VERSION 5.8 ;
BUSBITCHARS "[]" ;
DIVIDERCHAR "/" ;
UNITS
    DATABASE MICRONS 1000 ;
END UNITS

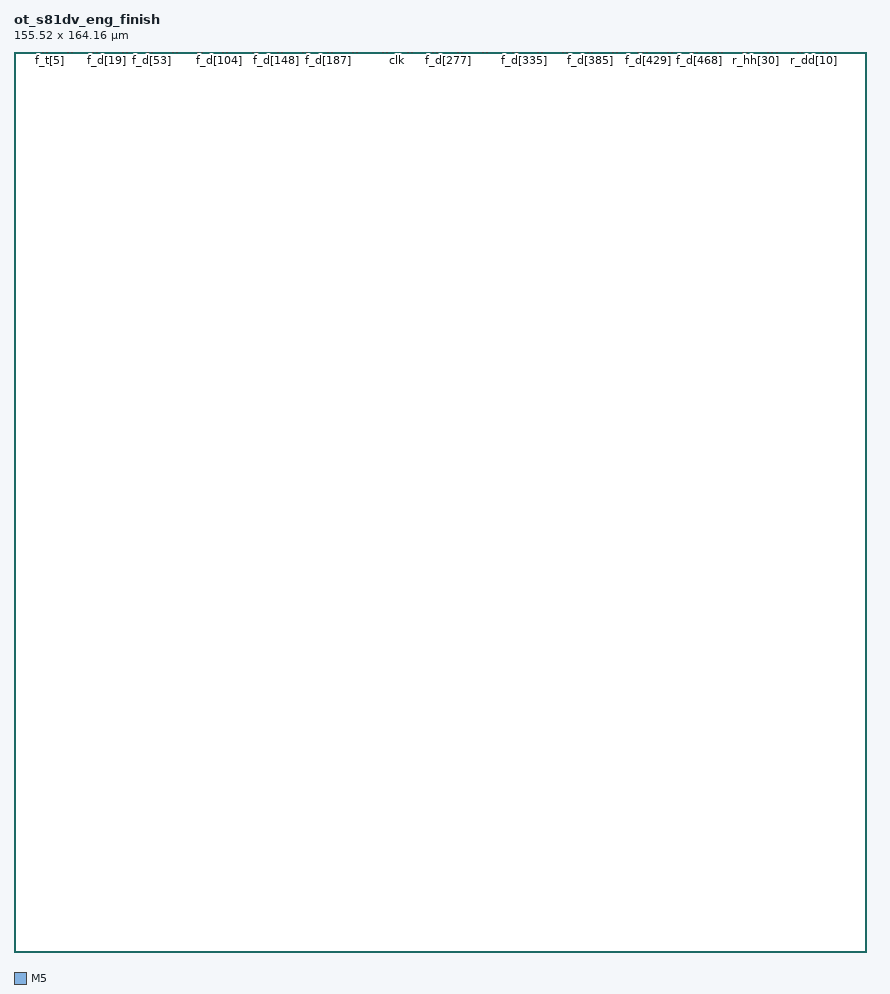
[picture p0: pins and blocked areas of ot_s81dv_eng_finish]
MACRO ot_s81dv_eng_finish
  FOREIGN ot_s81dv_eng_finish 0 0 ;
  CLASS BLOCK ;
  SIZE 155.52 BY 164.16 ;
  PIN go
    DIRECTION INPUT ;
    USE SIGNAL ;
    PORT
      LAYER M5 ;
        RECT 4.3200 164.0760 4.3440 164.1600 ;
    END
  END go
  PIN f_v[0]
    DIRECTION INPUT ;
    USE SIGNAL ;
    PORT
      LAYER M5 ;
        RECT 4.5600 164.0760 4.5840 164.1600 ;
    END
  END f_v[0]
  PIN f_v[1]
    DIRECTION INPUT ;
    USE SIGNAL ;
    PORT
      LAYER M5 ;
        RECT 4.8000 164.0760 4.8240 164.1600 ;
    END
  END f_v[1]
  PIN f_v[2]
    DIRECTION INPUT ;
    USE SIGNAL ;
    PORT
      LAYER M5 ;
        RECT 5.0400 164.0760 5.0640 164.1600 ;
    END
  END f_v[2]
  PIN f_t[0]
    DIRECTION INPUT ;
    USE SIGNAL ;
    PORT
      LAYER M5 ;
        RECT 5.2800 164.0760 5.3040 164.1600 ;
    END
  END f_t[0]
  PIN f_t[1]
    DIRECTION INPUT ;
    USE SIGNAL ;
    PORT
      LAYER M5 ;
        RECT 5.5200 164.0760 5.5440 164.1600 ;
    END
  END f_t[1]
  PIN f_t[2]
    DIRECTION INPUT ;
    USE SIGNAL ;
    PORT
      LAYER M5 ;
        RECT 5.7600 164.0760 5.7840 164.1600 ;
    END
  END f_t[2]
  PIN f_t[3]
    DIRECTION INPUT ;
    USE SIGNAL ;
    PORT
      LAYER M5 ;
        RECT 6.0000 164.0760 6.0240 164.1600 ;
    END
  END f_t[3]
  PIN f_t[4]
    DIRECTION INPUT ;
    USE SIGNAL ;
    PORT
      LAYER M5 ;
        RECT 6.2400 164.0760 6.2640 164.1600 ;
    END
  END f_t[4]
  PIN f_t[5]
    DIRECTION INPUT ;
    USE SIGNAL ;
    PORT
      LAYER M5 ;
        RECT 6.4800 164.0760 6.5040 164.1600 ;
    END
  END f_t[5]
  PIN f_base[0]
    DIRECTION INPUT ;
    USE SIGNAL ;
    PORT
      LAYER M5 ;
        RECT 6.7200 164.0760 6.7440 164.1600 ;
    END
  END f_base[0]
  PIN f_base[1]
    DIRECTION INPUT ;
    USE SIGNAL ;
    PORT
      LAYER M5 ;
        RECT 6.9600 164.0760 6.9840 164.1600 ;
    END
  END f_base[1]
  PIN f_base[2]
    DIRECTION INPUT ;
    USE SIGNAL ;
    PORT
      LAYER M5 ;
        RECT 7.2000 164.0760 7.2240 164.1600 ;
    END
  END f_base[2]
  PIN f_base[3]
    DIRECTION INPUT ;
    USE SIGNAL ;
    PORT
      LAYER M5 ;
        RECT 7.4400 164.0760 7.4640 164.1600 ;
    END
  END f_base[3]
  PIN f_base[4]
    DIRECTION INPUT ;
    USE SIGNAL ;
    PORT
      LAYER M5 ;
        RECT 7.6800 164.0760 7.7040 164.1600 ;
    END
  END f_base[4]
  PIN f_base[5]
    DIRECTION INPUT ;
    USE SIGNAL ;
    PORT
      LAYER M5 ;
        RECT 7.9200 164.0760 7.9440 164.1600 ;
    END
  END f_base[5]
  PIN f_base[6]
    DIRECTION INPUT ;
    USE SIGNAL ;
    PORT
      LAYER M5 ;
        RECT 8.1600 164.0760 8.1840 164.1600 ;
    END
  END f_base[6]
  PIN f_base[7]
    DIRECTION INPUT ;
    USE SIGNAL ;
    PORT
      LAYER M5 ;
        RECT 8.4000 164.0760 8.4240 164.1600 ;
    END
  END f_base[7]
  PIN f_base[8]
    DIRECTION INPUT ;
    USE SIGNAL ;
    PORT
      LAYER M5 ;
        RECT 8.6400 164.0760 8.6640 164.1600 ;
    END
  END f_base[8]
  PIN f_base[9]
    DIRECTION INPUT ;
    USE SIGNAL ;
    PORT
      LAYER M5 ;
        RECT 8.8800 164.0760 8.9040 164.1600 ;
    END
  END f_base[9]
  PIN f_base[10]
    DIRECTION INPUT ;
    USE SIGNAL ;
    PORT
      LAYER M5 ;
        RECT 9.1200 164.0760 9.1440 164.1600 ;
    END
  END f_base[10]
  PIN f_base[11]
    DIRECTION INPUT ;
    USE SIGNAL ;
    PORT
      LAYER M5 ;
        RECT 9.3600 164.0760 9.3840 164.1600 ;
    END
  END f_base[11]
  PIN f_base[12]
    DIRECTION INPUT ;
    USE SIGNAL ;
    PORT
      LAYER M5 ;
        RECT 9.6000 164.0760 9.6240 164.1600 ;
    END
  END f_base[12]
  PIN f_base[13]
    DIRECTION INPUT ;
    USE SIGNAL ;
    PORT
      LAYER M5 ;
        RECT 9.8400 164.0760 9.8640 164.1600 ;
    END
  END f_base[13]
  PIN f_base[14]
    DIRECTION INPUT ;
    USE SIGNAL ;
    PORT
      LAYER M5 ;
        RECT 10.0800 164.0760 10.1040 164.1600 ;
    END
  END f_base[14]
  PIN f_base[15]
    DIRECTION INPUT ;
    USE SIGNAL ;
    PORT
      LAYER M5 ;
        RECT 10.3200 164.0760 10.3440 164.1600 ;
    END
  END f_base[15]
  PIN f_base[16]
    DIRECTION INPUT ;
    USE SIGNAL ;
    PORT
      LAYER M5 ;
        RECT 10.5600 164.0760 10.5840 164.1600 ;
    END
  END f_base[16]
  PIN f_base[17]
    DIRECTION INPUT ;
    USE SIGNAL ;
    PORT
      LAYER M5 ;
        RECT 10.8000 164.0760 10.8240 164.1600 ;
    END
  END f_base[17]
  PIN f_base[18]
    DIRECTION INPUT ;
    USE SIGNAL ;
    PORT
      LAYER M5 ;
        RECT 11.0400 164.0760 11.0640 164.1600 ;
    END
  END f_base[18]
  PIN f_base[19]
    DIRECTION INPUT ;
    USE SIGNAL ;
    PORT
      LAYER M5 ;
        RECT 11.2800 164.0760 11.3040 164.1600 ;
    END
  END f_base[19]
  PIN f_base[20]
    DIRECTION INPUT ;
    USE SIGNAL ;
    PORT
      LAYER M5 ;
        RECT 11.5200 164.0760 11.5440 164.1600 ;
    END
  END f_base[20]
  PIN f_base[21]
    DIRECTION INPUT ;
    USE SIGNAL ;
    PORT
      LAYER M5 ;
        RECT 11.7600 164.0760 11.7840 164.1600 ;
    END
  END f_base[21]
  PIN f_base[22]
    DIRECTION INPUT ;
    USE SIGNAL ;
    PORT
      LAYER M5 ;
        RECT 12.0000 164.0760 12.0240 164.1600 ;
    END
  END f_base[22]
  PIN f_base[23]
    DIRECTION INPUT ;
    USE SIGNAL ;
    PORT
      LAYER M5 ;
        RECT 12.2400 164.0760 12.2640 164.1600 ;
    END
  END f_base[23]
  PIN f_d[0]
    DIRECTION INPUT ;
    USE SIGNAL ;
    PORT
      LAYER M5 ;
        RECT 12.4800 164.0760 12.5040 164.1600 ;
    END
  END f_d[0]
  PIN f_d[1]
    DIRECTION INPUT ;
    USE SIGNAL ;
    PORT
      LAYER M5 ;
        RECT 12.7200 164.0760 12.7440 164.1600 ;
    END
  END f_d[1]
  PIN f_d[2]
    DIRECTION INPUT ;
    USE SIGNAL ;
    PORT
      LAYER M5 ;
        RECT 12.9600 164.0760 12.9840 164.1600 ;
    END
  END f_d[2]
  PIN f_d[3]
    DIRECTION INPUT ;
    USE SIGNAL ;
    PORT
      LAYER M5 ;
        RECT 13.2000 164.0760 13.2240 164.1600 ;
    END
  END f_d[3]
  PIN f_d[4]
    DIRECTION INPUT ;
    USE SIGNAL ;
    PORT
      LAYER M5 ;
        RECT 13.4400 164.0760 13.4640 164.1600 ;
    END
  END f_d[4]
  PIN f_d[5]
    DIRECTION INPUT ;
    USE SIGNAL ;
    PORT
      LAYER M5 ;
        RECT 13.6800 164.0760 13.7040 164.1600 ;
    END
  END f_d[5]
  PIN f_d[6]
    DIRECTION INPUT ;
    USE SIGNAL ;
    PORT
      LAYER M5 ;
        RECT 13.9200 164.0760 13.9440 164.1600 ;
    END
  END f_d[6]
  PIN f_d[7]
    DIRECTION INPUT ;
    USE SIGNAL ;
    PORT
      LAYER M5 ;
        RECT 14.1600 164.0760 14.1840 164.1600 ;
    END
  END f_d[7]
  PIN f_d[8]
    DIRECTION INPUT ;
    USE SIGNAL ;
    PORT
      LAYER M5 ;
        RECT 14.4000 164.0760 14.4240 164.1600 ;
    END
  END f_d[8]
  PIN f_d[9]
    DIRECTION INPUT ;
    USE SIGNAL ;
    PORT
      LAYER M5 ;
        RECT 14.6400 164.0760 14.6640 164.1600 ;
    END
  END f_d[9]
  PIN f_d[10]
    DIRECTION INPUT ;
    USE SIGNAL ;
    PORT
      LAYER M5 ;
        RECT 14.8800 164.0760 14.9040 164.1600 ;
    END
  END f_d[10]
  PIN f_d[11]
    DIRECTION INPUT ;
    USE SIGNAL ;
    PORT
      LAYER M5 ;
        RECT 15.1200 164.0760 15.1440 164.1600 ;
    END
  END f_d[11]
  PIN f_d[12]
    DIRECTION INPUT ;
    USE SIGNAL ;
    PORT
      LAYER M5 ;
        RECT 15.3600 164.0760 15.3840 164.1600 ;
    END
  END f_d[12]
  PIN f_d[13]
    DIRECTION INPUT ;
    USE SIGNAL ;
    PORT
      LAYER M5 ;
        RECT 15.6000 164.0760 15.6240 164.1600 ;
    END
  END f_d[13]
  PIN f_d[14]
    DIRECTION INPUT ;
    USE SIGNAL ;
    PORT
      LAYER M5 ;
        RECT 15.8400 164.0760 15.8640 164.1600 ;
    END
  END f_d[14]
  PIN f_d[15]
    DIRECTION INPUT ;
    USE SIGNAL ;
    PORT
      LAYER M5 ;
        RECT 16.0800 164.0760 16.1040 164.1600 ;
    END
  END f_d[15]
  PIN f_d[16]
    DIRECTION INPUT ;
    USE SIGNAL ;
    PORT
      LAYER M5 ;
        RECT 16.3200 164.0760 16.3440 164.1600 ;
    END
  END f_d[16]
  PIN f_d[17]
    DIRECTION INPUT ;
    USE SIGNAL ;
    PORT
      LAYER M5 ;
        RECT 16.5600 164.0760 16.5840 164.1600 ;
    END
  END f_d[17]
  PIN f_d[18]
    DIRECTION INPUT ;
    USE SIGNAL ;
    PORT
      LAYER M5 ;
        RECT 16.7520 164.0760 16.7760 164.1600 ;
    END
  END f_d[18]
  PIN f_d[19]
    DIRECTION INPUT ;
    USE SIGNAL ;
    PORT
      LAYER M5 ;
        RECT 16.9920 164.0760 17.0160 164.1600 ;
    END
  END f_d[19]
  PIN f_d[20]
    DIRECTION INPUT ;
    USE SIGNAL ;
    PORT
      LAYER M5 ;
        RECT 17.2320 164.0760 17.2560 164.1600 ;
    END
  END f_d[20]
  PIN f_d[21]
    DIRECTION INPUT ;
    USE SIGNAL ;
    PORT
      LAYER M5 ;
        RECT 17.4720 164.0760 17.4960 164.1600 ;
    END
  END f_d[21]
  PIN f_d[22]
    DIRECTION INPUT ;
    USE SIGNAL ;
    PORT
      LAYER M5 ;
        RECT 17.7120 164.0760 17.7360 164.1600 ;
    END
  END f_d[22]
  PIN f_d[23]
    DIRECTION INPUT ;
    USE SIGNAL ;
    PORT
      LAYER M5 ;
        RECT 17.9520 164.0760 17.9760 164.1600 ;
    END
  END f_d[23]
  PIN f_d[24]
    DIRECTION INPUT ;
    USE SIGNAL ;
    PORT
      LAYER M5 ;
        RECT 18.1920 164.0760 18.2160 164.1600 ;
    END
  END f_d[24]
  PIN f_d[25]
    DIRECTION INPUT ;
    USE SIGNAL ;
    PORT
      LAYER M5 ;
        RECT 18.4320 164.0760 18.4560 164.1600 ;
    END
  END f_d[25]
  PIN f_d[26]
    DIRECTION INPUT ;
    USE SIGNAL ;
    PORT
      LAYER M5 ;
        RECT 18.6720 164.0760 18.6960 164.1600 ;
    END
  END f_d[26]
  PIN f_d[27]
    DIRECTION INPUT ;
    USE SIGNAL ;
    PORT
      LAYER M5 ;
        RECT 18.9120 164.0760 18.9360 164.1600 ;
    END
  END f_d[27]
  PIN f_d[28]
    DIRECTION INPUT ;
    USE SIGNAL ;
    PORT
      LAYER M5 ;
        RECT 19.1520 164.0760 19.1760 164.1600 ;
    END
  END f_d[28]
  PIN f_d[29]
    DIRECTION INPUT ;
    USE SIGNAL ;
    PORT
      LAYER M5 ;
        RECT 19.3920 164.0760 19.4160 164.1600 ;
    END
  END f_d[29]
  PIN f_d[30]
    DIRECTION INPUT ;
    USE SIGNAL ;
    PORT
      LAYER M5 ;
        RECT 19.6320 164.0760 19.6560 164.1600 ;
    END
  END f_d[30]
  PIN f_d[31]
    DIRECTION INPUT ;
    USE SIGNAL ;
    PORT
      LAYER M5 ;
        RECT 19.8720 164.0760 19.8960 164.1600 ;
    END
  END f_d[31]
  PIN f_d[32]
    DIRECTION INPUT ;
    USE SIGNAL ;
    PORT
      LAYER M5 ;
        RECT 20.1120 164.0760 20.1360 164.1600 ;
    END
  END f_d[32]
  PIN f_d[33]
    DIRECTION INPUT ;
    USE SIGNAL ;
    PORT
      LAYER M5 ;
        RECT 20.3520 164.0760 20.3760 164.1600 ;
    END
  END f_d[33]
  PIN f_d[34]
    DIRECTION INPUT ;
    USE SIGNAL ;
    PORT
      LAYER M5 ;
        RECT 20.5920 164.0760 20.6160 164.1600 ;
    END
  END f_d[34]
  PIN f_d[35]
    DIRECTION INPUT ;
    USE SIGNAL ;
    PORT
      LAYER M5 ;
        RECT 20.8320 164.0760 20.8560 164.1600 ;
    END
  END f_d[35]
  PIN f_d[36]
    DIRECTION INPUT ;
    USE SIGNAL ;
    PORT
      LAYER M5 ;
        RECT 21.0720 164.0760 21.0960 164.1600 ;
    END
  END f_d[36]
  PIN f_d[37]
    DIRECTION INPUT ;
    USE SIGNAL ;
    PORT
      LAYER M5 ;
        RECT 21.3120 164.0760 21.3360 164.1600 ;
    END
  END f_d[37]
  PIN f_d[38]
    DIRECTION INPUT ;
    USE SIGNAL ;
    PORT
      LAYER M5 ;
        RECT 21.5520 164.0760 21.5760 164.1600 ;
    END
  END f_d[38]
  PIN f_d[39]
    DIRECTION INPUT ;
    USE SIGNAL ;
    PORT
      LAYER M5 ;
        RECT 21.7920 164.0760 21.8160 164.1600 ;
    END
  END f_d[39]
  PIN f_d[40]
    DIRECTION INPUT ;
    USE SIGNAL ;
    PORT
      LAYER M5 ;
        RECT 22.0320 164.0760 22.0560 164.1600 ;
    END
  END f_d[40]
  PIN f_d[41]
    DIRECTION INPUT ;
    USE SIGNAL ;
    PORT
      LAYER M5 ;
        RECT 22.2720 164.0760 22.2960 164.1600 ;
    END
  END f_d[41]
  PIN f_d[42]
    DIRECTION INPUT ;
    USE SIGNAL ;
    PORT
      LAYER M5 ;
        RECT 22.5120 164.0760 22.5360 164.1600 ;
    END
  END f_d[42]
  PIN f_d[43]
    DIRECTION INPUT ;
    USE SIGNAL ;
    PORT
      LAYER M5 ;
        RECT 22.7520 164.0760 22.7760 164.1600 ;
    END
  END f_d[43]
  PIN f_d[44]
    DIRECTION INPUT ;
    USE SIGNAL ;
    PORT
      LAYER M5 ;
        RECT 22.9920 164.0760 23.0160 164.1600 ;
    END
  END f_d[44]
  PIN f_d[45]
    DIRECTION INPUT ;
    USE SIGNAL ;
    PORT
      LAYER M5 ;
        RECT 23.2320 164.0760 23.2560 164.1600 ;
    END
  END f_d[45]
  PIN f_d[46]
    DIRECTION INPUT ;
    USE SIGNAL ;
    PORT
      LAYER M5 ;
        RECT 23.4720 164.0760 23.4960 164.1600 ;
    END
  END f_d[46]
  PIN f_d[47]
    DIRECTION INPUT ;
    USE SIGNAL ;
    PORT
      LAYER M5 ;
        RECT 23.7120 164.0760 23.7360 164.1600 ;
    END
  END f_d[47]
  PIN f_d[48]
    DIRECTION INPUT ;
    USE SIGNAL ;
    PORT
      LAYER M5 ;
        RECT 23.9520 164.0760 23.9760 164.1600 ;
    END
  END f_d[48]
  PIN f_d[49]
    DIRECTION INPUT ;
    USE SIGNAL ;
    PORT
      LAYER M5 ;
        RECT 24.1920 164.0760 24.2160 164.1600 ;
    END
  END f_d[49]
  PIN f_d[50]
    DIRECTION INPUT ;
    USE SIGNAL ;
    PORT
      LAYER M5 ;
        RECT 24.4320 164.0760 24.4560 164.1600 ;
    END
  END f_d[50]
  PIN f_d[51]
    DIRECTION INPUT ;
    USE SIGNAL ;
    PORT
      LAYER M5 ;
        RECT 24.6720 164.0760 24.6960 164.1600 ;
    END
  END f_d[51]
  PIN f_d[52]
    DIRECTION INPUT ;
    USE SIGNAL ;
    PORT
      LAYER M5 ;
        RECT 24.9120 164.0760 24.9360 164.1600 ;
    END
  END f_d[52]
  PIN f_d[53]
    DIRECTION INPUT ;
    USE SIGNAL ;
    PORT
      LAYER M5 ;
        RECT 25.1520 164.0760 25.1760 164.1600 ;
    END
  END f_d[53]
  PIN f_d[54]
    DIRECTION INPUT ;
    USE SIGNAL ;
    PORT
      LAYER M5 ;
        RECT 25.3920 164.0760 25.4160 164.1600 ;
    END
  END f_d[54]
  PIN f_d[55]
    DIRECTION INPUT ;
    USE SIGNAL ;
    PORT
      LAYER M5 ;
        RECT 25.6320 164.0760 25.6560 164.1600 ;
    END
  END f_d[55]
  PIN f_d[56]
    DIRECTION INPUT ;
    USE SIGNAL ;
    PORT
      LAYER M5 ;
        RECT 25.8720 164.0760 25.8960 164.1600 ;
    END
  END f_d[56]
  PIN f_d[57]
    DIRECTION INPUT ;
    USE SIGNAL ;
    PORT
      LAYER M5 ;
        RECT 26.1120 164.0760 26.1360 164.1600 ;
    END
  END f_d[57]
  PIN f_d[58]
    DIRECTION INPUT ;
    USE SIGNAL ;
    PORT
      LAYER M5 ;
        RECT 26.3520 164.0760 26.3760 164.1600 ;
    END
  END f_d[58]
  PIN f_d[59]
    DIRECTION INPUT ;
    USE SIGNAL ;
    PORT
      LAYER M5 ;
        RECT 26.5920 164.0760 26.6160 164.1600 ;
    END
  END f_d[59]
  PIN f_d[60]
    DIRECTION INPUT ;
    USE SIGNAL ;
    PORT
      LAYER M5 ;
        RECT 26.8320 164.0760 26.8560 164.1600 ;
    END
  END f_d[60]
  PIN f_d[61]
    DIRECTION INPUT ;
    USE SIGNAL ;
    PORT
      LAYER M5 ;
        RECT 27.0720 164.0760 27.0960 164.1600 ;
    END
  END f_d[61]
  PIN f_d[62]
    DIRECTION INPUT ;
    USE SIGNAL ;
    PORT
      LAYER M5 ;
        RECT 27.3120 164.0760 27.3360 164.1600 ;
    END
  END f_d[62]
  PIN f_d[63]
    DIRECTION INPUT ;
    USE SIGNAL ;
    PORT
      LAYER M5 ;
        RECT 27.5520 164.0760 27.5760 164.1600 ;
    END
  END f_d[63]
  PIN f_d[64]
    DIRECTION INPUT ;
    USE SIGNAL ;
    PORT
      LAYER M5 ;
        RECT 27.7920 164.0760 27.8160 164.1600 ;
    END
  END f_d[64]
  PIN f_d[65]
    DIRECTION INPUT ;
    USE SIGNAL ;
    PORT
      LAYER M5 ;
        RECT 28.0320 164.0760 28.0560 164.1600 ;
    END
  END f_d[65]
  PIN f_d[66]
    DIRECTION INPUT ;
    USE SIGNAL ;
    PORT
      LAYER M5 ;
        RECT 28.2720 164.0760 28.2960 164.1600 ;
    END
  END f_d[66]
  PIN f_d[67]
    DIRECTION INPUT ;
    USE SIGNAL ;
    PORT
      LAYER M5 ;
        RECT 28.5120 164.0760 28.5360 164.1600 ;
    END
  END f_d[67]
  PIN f_d[68]
    DIRECTION INPUT ;
    USE SIGNAL ;
    PORT
      LAYER M5 ;
        RECT 28.7520 164.0760 28.7760 164.1600 ;
    END
  END f_d[68]
  PIN f_d[69]
    DIRECTION INPUT ;
    USE SIGNAL ;
    PORT
      LAYER M5 ;
        RECT 28.9920 164.0760 29.0160 164.1600 ;
    END
  END f_d[69]
  PIN f_d[70]
    DIRECTION INPUT ;
    USE SIGNAL ;
    PORT
      LAYER M5 ;
        RECT 29.2320 164.0760 29.2560 164.1600 ;
    END
  END f_d[70]
  PIN f_d[71]
    DIRECTION INPUT ;
    USE SIGNAL ;
    PORT
      LAYER M5 ;
        RECT 29.4720 164.0760 29.4960 164.1600 ;
    END
  END f_d[71]
  PIN f_d[72]
    DIRECTION INPUT ;
    USE SIGNAL ;
    PORT
      LAYER M5 ;
        RECT 29.7120 164.0760 29.7360 164.1600 ;
    END
  END f_d[72]
  PIN f_d[73]
    DIRECTION INPUT ;
    USE SIGNAL ;
    PORT
      LAYER M5 ;
        RECT 29.9520 164.0760 29.9760 164.1600 ;
    END
  END f_d[73]
  PIN f_d[74]
    DIRECTION INPUT ;
    USE SIGNAL ;
    PORT
      LAYER M5 ;
        RECT 30.1920 164.0760 30.2160 164.1600 ;
    END
  END f_d[74]
  PIN f_d[75]
    DIRECTION INPUT ;
    USE SIGNAL ;
    PORT
      LAYER M5 ;
        RECT 30.4320 164.0760 30.4560 164.1600 ;
    END
  END f_d[75]
  PIN f_d[76]
    DIRECTION INPUT ;
    USE SIGNAL ;
    PORT
      LAYER M5 ;
        RECT 30.6720 164.0760 30.6960 164.1600 ;
    END
  END f_d[76]
  PIN f_d[77]
    DIRECTION INPUT ;
    USE SIGNAL ;
    PORT
      LAYER M5 ;
        RECT 30.9120 164.0760 30.9360 164.1600 ;
    END
  END f_d[77]
  PIN f_d[78]
    DIRECTION INPUT ;
    USE SIGNAL ;
    PORT
      LAYER M5 ;
        RECT 31.1520 164.0760 31.1760 164.1600 ;
    END
  END f_d[78]
  PIN f_d[79]
    DIRECTION INPUT ;
    USE SIGNAL ;
    PORT
      LAYER M5 ;
        RECT 31.3920 164.0760 31.4160 164.1600 ;
    END
  END f_d[79]
  PIN f_d[80]
    DIRECTION INPUT ;
    USE SIGNAL ;
    PORT
      LAYER M5 ;
        RECT 31.6320 164.0760 31.6560 164.1600 ;
    END
  END f_d[80]
  PIN f_d[81]
    DIRECTION INPUT ;
    USE SIGNAL ;
    PORT
      LAYER M5 ;
        RECT 31.8720 164.0760 31.8960 164.1600 ;
    END
  END f_d[81]
  PIN f_d[82]
    DIRECTION INPUT ;
    USE SIGNAL ;
    PORT
      LAYER M5 ;
        RECT 32.1120 164.0760 32.1360 164.1600 ;
    END
  END f_d[82]
  PIN f_d[83]
    DIRECTION INPUT ;
    USE SIGNAL ;
    PORT
      LAYER M5 ;
        RECT 32.3520 164.0760 32.3760 164.1600 ;
    END
  END f_d[83]
  PIN f_d[84]
    DIRECTION INPUT ;
    USE SIGNAL ;
    PORT
      LAYER M5 ;
        RECT 32.5920 164.0760 32.6160 164.1600 ;
    END
  END f_d[84]
  PIN f_d[85]
    DIRECTION INPUT ;
    USE SIGNAL ;
    PORT
      LAYER M5 ;
        RECT 32.8320 164.0760 32.8560 164.1600 ;
    END
  END f_d[85]
  PIN f_d[86]
    DIRECTION INPUT ;
    USE SIGNAL ;
    PORT
      LAYER M5 ;
        RECT 33.0720 164.0760 33.0960 164.1600 ;
    END
  END f_d[86]
  PIN f_d[87]
    DIRECTION INPUT ;
    USE SIGNAL ;
    PORT
      LAYER M5 ;
        RECT 33.3120 164.0760 33.3360 164.1600 ;
    END
  END f_d[87]
  PIN f_d[88]
    DIRECTION INPUT ;
    USE SIGNAL ;
    PORT
      LAYER M5 ;
        RECT 33.5520 164.0760 33.5760 164.1600 ;
    END
  END f_d[88]
  PIN f_d[89]
    DIRECTION INPUT ;
    USE SIGNAL ;
    PORT
      LAYER M5 ;
        RECT 33.7920 164.0760 33.8160 164.1600 ;
    END
  END f_d[89]
  PIN f_d[90]
    DIRECTION INPUT ;
    USE SIGNAL ;
    PORT
      LAYER M5 ;
        RECT 34.0320 164.0760 34.0560 164.1600 ;
    END
  END f_d[90]
  PIN f_d[91]
    DIRECTION INPUT ;
    USE SIGNAL ;
    PORT
      LAYER M5 ;
        RECT 34.2720 164.0760 34.2960 164.1600 ;
    END
  END f_d[91]
  PIN f_d[92]
    DIRECTION INPUT ;
    USE SIGNAL ;
    PORT
      LAYER M5 ;
        RECT 34.5120 164.0760 34.5360 164.1600 ;
    END
  END f_d[92]
  PIN f_d[93]
    DIRECTION INPUT ;
    USE SIGNAL ;
    PORT
      LAYER M5 ;
        RECT 34.7520 164.0760 34.7760 164.1600 ;
    END
  END f_d[93]
  PIN f_d[94]
    DIRECTION INPUT ;
    USE SIGNAL ;
    PORT
      LAYER M5 ;
        RECT 34.9920 164.0760 35.0160 164.1600 ;
    END
  END f_d[94]
  PIN f_d[95]
    DIRECTION INPUT ;
    USE SIGNAL ;
    PORT
      LAYER M5 ;
        RECT 35.2320 164.0760 35.2560 164.1600 ;
    END
  END f_d[95]
  PIN f_d[96]
    DIRECTION INPUT ;
    USE SIGNAL ;
    PORT
      LAYER M5 ;
        RECT 35.4720 164.0760 35.4960 164.1600 ;
    END
  END f_d[96]
  PIN f_d[97]
    DIRECTION INPUT ;
    USE SIGNAL ;
    PORT
      LAYER M5 ;
        RECT 35.7120 164.0760 35.7360 164.1600 ;
    END
  END f_d[97]
  PIN f_d[98]
    DIRECTION INPUT ;
    USE SIGNAL ;
    PORT
      LAYER M5 ;
        RECT 35.9520 164.0760 35.9760 164.1600 ;
    END
  END f_d[98]
  PIN f_d[99]
    DIRECTION INPUT ;
    USE SIGNAL ;
    PORT
      LAYER M5 ;
        RECT 36.1920 164.0760 36.2160 164.1600 ;
    END
  END f_d[99]
  PIN f_d[100]
    DIRECTION INPUT ;
    USE SIGNAL ;
    PORT
      LAYER M5 ;
        RECT 36.4320 164.0760 36.4560 164.1600 ;
    END
  END f_d[100]
  PIN f_d[101]
    DIRECTION INPUT ;
    USE SIGNAL ;
    PORT
      LAYER M5 ;
        RECT 36.6720 164.0760 36.6960 164.1600 ;
    END
  END f_d[101]
  PIN f_d[102]
    DIRECTION INPUT ;
    USE SIGNAL ;
    PORT
      LAYER M5 ;
        RECT 36.9120 164.0760 36.9360 164.1600 ;
    END
  END f_d[102]
  PIN f_d[103]
    DIRECTION INPUT ;
    USE SIGNAL ;
    PORT
      LAYER M5 ;
        RECT 37.1520 164.0760 37.1760 164.1600 ;
    END
  END f_d[103]
  PIN f_d[104]
    DIRECTION INPUT ;
    USE SIGNAL ;
    PORT
      LAYER M5 ;
        RECT 37.3920 164.0760 37.4160 164.1600 ;
    END
  END f_d[104]
  PIN f_d[105]
    DIRECTION INPUT ;
    USE SIGNAL ;
    PORT
      LAYER M5 ;
        RECT 37.6320 164.0760 37.6560 164.1600 ;
    END
  END f_d[105]
  PIN f_d[106]
    DIRECTION INPUT ;
    USE SIGNAL ;
    PORT
      LAYER M5 ;
        RECT 37.8720 164.0760 37.8960 164.1600 ;
    END
  END f_d[106]
  PIN f_d[107]
    DIRECTION INPUT ;
    USE SIGNAL ;
    PORT
      LAYER M5 ;
        RECT 38.1120 164.0760 38.1360 164.1600 ;
    END
  END f_d[107]
  PIN f_d[108]
    DIRECTION INPUT ;
    USE SIGNAL ;
    PORT
      LAYER M5 ;
        RECT 38.3520 164.0760 38.3760 164.1600 ;
    END
  END f_d[108]
  PIN f_d[109]
    DIRECTION INPUT ;
    USE SIGNAL ;
    PORT
      LAYER M5 ;
        RECT 38.5920 164.0760 38.6160 164.1600 ;
    END
  END f_d[109]
  PIN f_d[110]
    DIRECTION INPUT ;
    USE SIGNAL ;
    PORT
      LAYER M5 ;
        RECT 38.8320 164.0760 38.8560 164.1600 ;
    END
  END f_d[110]
  PIN f_d[111]
    DIRECTION INPUT ;
    USE SIGNAL ;
    PORT
      LAYER M5 ;
        RECT 39.0720 164.0760 39.0960 164.1600 ;
    END
  END f_d[111]
  PIN f_d[112]
    DIRECTION INPUT ;
    USE SIGNAL ;
    PORT
      LAYER M5 ;
        RECT 39.3120 164.0760 39.3360 164.1600 ;
    END
  END f_d[112]
  PIN f_d[113]
    DIRECTION INPUT ;
    USE SIGNAL ;
    PORT
      LAYER M5 ;
        RECT 39.5520 164.0760 39.5760 164.1600 ;
    END
  END f_d[113]
  PIN f_d[114]
    DIRECTION INPUT ;
    USE SIGNAL ;
    PORT
      LAYER M5 ;
        RECT 39.7920 164.0760 39.8160 164.1600 ;
    END
  END f_d[114]
  PIN f_d[115]
    DIRECTION INPUT ;
    USE SIGNAL ;
    PORT
      LAYER M5 ;
        RECT 40.0320 164.0760 40.0560 164.1600 ;
    END
  END f_d[115]
  PIN f_d[116]
    DIRECTION INPUT ;
    USE SIGNAL ;
    PORT
      LAYER M5 ;
        RECT 40.2720 164.0760 40.2960 164.1600 ;
    END
  END f_d[116]
  PIN f_d[117]
    DIRECTION INPUT ;
    USE SIGNAL ;
    PORT
      LAYER M5 ;
        RECT 40.5120 164.0760 40.5360 164.1600 ;
    END
  END f_d[117]
  PIN f_d[118]
    DIRECTION INPUT ;
    USE SIGNAL ;
    PORT
      LAYER M5 ;
        RECT 40.7520 164.0760 40.7760 164.1600 ;
    END
  END f_d[118]
  PIN f_d[119]
    DIRECTION INPUT ;
    USE SIGNAL ;
    PORT
      LAYER M5 ;
        RECT 40.9920 164.0760 41.0160 164.1600 ;
    END
  END f_d[119]
  PIN f_d[120]
    DIRECTION INPUT ;
    USE SIGNAL ;
    PORT
      LAYER M5 ;
        RECT 41.1840 164.0760 41.2080 164.1600 ;
    END
  END f_d[120]
  PIN f_d[121]
    DIRECTION INPUT ;
    USE SIGNAL ;
    PORT
      LAYER M5 ;
        RECT 41.4240 164.0760 41.4480 164.1600 ;
    END
  END f_d[121]
  PIN f_d[122]
    DIRECTION INPUT ;
    USE SIGNAL ;
    PORT
      LAYER M5 ;
        RECT 41.6640 164.0760 41.6880 164.1600 ;
    END
  END f_d[122]
  PIN f_d[123]
    DIRECTION INPUT ;
    USE SIGNAL ;
    PORT
      LAYER M5 ;
        RECT 41.9040 164.0760 41.9280 164.1600 ;
    END
  END f_d[123]
  PIN f_d[124]
    DIRECTION INPUT ;
    USE SIGNAL ;
    PORT
      LAYER M5 ;
        RECT 42.1440 164.0760 42.1680 164.1600 ;
    END
  END f_d[124]
  PIN f_d[125]
    DIRECTION INPUT ;
    USE SIGNAL ;
    PORT
      LAYER M5 ;
        RECT 42.3840 164.0760 42.4080 164.1600 ;
    END
  END f_d[125]
  PIN f_d[126]
    DIRECTION INPUT ;
    USE SIGNAL ;
    PORT
      LAYER M5 ;
        RECT 42.6240 164.0760 42.6480 164.1600 ;
    END
  END f_d[126]
  PIN f_d[127]
    DIRECTION INPUT ;
    USE SIGNAL ;
    PORT
      LAYER M5 ;
        RECT 42.8640 164.0760 42.8880 164.1600 ;
    END
  END f_d[127]
  PIN f_d[128]
    DIRECTION INPUT ;
    USE SIGNAL ;
    PORT
      LAYER M5 ;
        RECT 43.1040 164.0760 43.1280 164.1600 ;
    END
  END f_d[128]
  PIN f_d[129]
    DIRECTION INPUT ;
    USE SIGNAL ;
    PORT
      LAYER M5 ;
        RECT 43.3440 164.0760 43.3680 164.1600 ;
    END
  END f_d[129]
  PIN f_d[130]
    DIRECTION INPUT ;
    USE SIGNAL ;
    PORT
      LAYER M5 ;
        RECT 43.5840 164.0760 43.6080 164.1600 ;
    END
  END f_d[130]
  PIN f_d[131]
    DIRECTION INPUT ;
    USE SIGNAL ;
    PORT
      LAYER M5 ;
        RECT 43.8240 164.0760 43.8480 164.1600 ;
    END
  END f_d[131]
  PIN f_d[132]
    DIRECTION INPUT ;
    USE SIGNAL ;
    PORT
      LAYER M5 ;
        RECT 44.0640 164.0760 44.0880 164.1600 ;
    END
  END f_d[132]
  PIN f_d[133]
    DIRECTION INPUT ;
    USE SIGNAL ;
    PORT
      LAYER M5 ;
        RECT 44.3040 164.0760 44.3280 164.1600 ;
    END
  END f_d[133]
  PIN f_d[134]
    DIRECTION INPUT ;
    USE SIGNAL ;
    PORT
      LAYER M5 ;
        RECT 44.5440 164.0760 44.5680 164.1600 ;
    END
  END f_d[134]
  PIN f_d[135]
    DIRECTION INPUT ;
    USE SIGNAL ;
    PORT
      LAYER M5 ;
        RECT 44.7840 164.0760 44.8080 164.1600 ;
    END
  END f_d[135]
  PIN f_d[136]
    DIRECTION INPUT ;
    USE SIGNAL ;
    PORT
      LAYER M5 ;
        RECT 45.0240 164.0760 45.0480 164.1600 ;
    END
  END f_d[136]
  PIN f_d[137]
    DIRECTION INPUT ;
    USE SIGNAL ;
    PORT
      LAYER M5 ;
        RECT 45.2640 164.0760 45.2880 164.1600 ;
    END
  END f_d[137]
  PIN f_d[138]
    DIRECTION INPUT ;
    USE SIGNAL ;
    PORT
      LAYER M5 ;
        RECT 45.5040 164.0760 45.5280 164.1600 ;
    END
  END f_d[138]
  PIN f_d[139]
    DIRECTION INPUT ;
    USE SIGNAL ;
    PORT
      LAYER M5 ;
        RECT 45.7440 164.0760 45.7680 164.1600 ;
    END
  END f_d[139]
  PIN f_d[140]
    DIRECTION INPUT ;
    USE SIGNAL ;
    PORT
      LAYER M5 ;
        RECT 45.9840 164.0760 46.0080 164.1600 ;
    END
  END f_d[140]
  PIN f_d[141]
    DIRECTION INPUT ;
    USE SIGNAL ;
    PORT
      LAYER M5 ;
        RECT 46.2240 164.0760 46.2480 164.1600 ;
    END
  END f_d[141]
  PIN f_d[142]
    DIRECTION INPUT ;
    USE SIGNAL ;
    PORT
      LAYER M5 ;
        RECT 46.4640 164.0760 46.4880 164.1600 ;
    END
  END f_d[142]
  PIN f_d[143]
    DIRECTION INPUT ;
    USE SIGNAL ;
    PORT
      LAYER M5 ;
        RECT 46.7040 164.0760 46.7280 164.1600 ;
    END
  END f_d[143]
  PIN f_d[144]
    DIRECTION INPUT ;
    USE SIGNAL ;
    PORT
      LAYER M5 ;
        RECT 46.9440 164.0760 46.9680 164.1600 ;
    END
  END f_d[144]
  PIN f_d[145]
    DIRECTION INPUT ;
    USE SIGNAL ;
    PORT
      LAYER M5 ;
        RECT 47.1840 164.0760 47.2080 164.1600 ;
    END
  END f_d[145]
  PIN f_d[146]
    DIRECTION INPUT ;
    USE SIGNAL ;
    PORT
      LAYER M5 ;
        RECT 47.4240 164.0760 47.4480 164.1600 ;
    END
  END f_d[146]
  PIN f_d[147]
    DIRECTION INPUT ;
    USE SIGNAL ;
    PORT
      LAYER M5 ;
        RECT 47.6640 164.0760 47.6880 164.1600 ;
    END
  END f_d[147]
  PIN f_d[148]
    DIRECTION INPUT ;
    USE SIGNAL ;
    PORT
      LAYER M5 ;
        RECT 47.9040 164.0760 47.9280 164.1600 ;
    END
  END f_d[148]
  PIN f_d[149]
    DIRECTION INPUT ;
    USE SIGNAL ;
    PORT
      LAYER M5 ;
        RECT 48.1440 164.0760 48.1680 164.1600 ;
    END
  END f_d[149]
  PIN f_d[150]
    DIRECTION INPUT ;
    USE SIGNAL ;
    PORT
      LAYER M5 ;
        RECT 48.3840 164.0760 48.4080 164.1600 ;
    END
  END f_d[150]
  PIN f_d[151]
    DIRECTION INPUT ;
    USE SIGNAL ;
    PORT
      LAYER M5 ;
        RECT 48.6240 164.0760 48.6480 164.1600 ;
    END
  END f_d[151]
  PIN f_d[152]
    DIRECTION INPUT ;
    USE SIGNAL ;
    PORT
      LAYER M5 ;
        RECT 48.8640 164.0760 48.8880 164.1600 ;
    END
  END f_d[152]
  PIN f_d[153]
    DIRECTION INPUT ;
    USE SIGNAL ;
    PORT
      LAYER M5 ;
        RECT 49.1040 164.0760 49.1280 164.1600 ;
    END
  END f_d[153]
  PIN f_d[154]
    DIRECTION INPUT ;
    USE SIGNAL ;
    PORT
      LAYER M5 ;
        RECT 49.3440 164.0760 49.3680 164.1600 ;
    END
  END f_d[154]
  PIN f_d[155]
    DIRECTION INPUT ;
    USE SIGNAL ;
    PORT
      LAYER M5 ;
        RECT 49.5840 164.0760 49.6080 164.1600 ;
    END
  END f_d[155]
  PIN f_d[156]
    DIRECTION INPUT ;
    USE SIGNAL ;
    PORT
      LAYER M5 ;
        RECT 49.8240 164.0760 49.8480 164.1600 ;
    END
  END f_d[156]
  PIN f_d[157]
    DIRECTION INPUT ;
    USE SIGNAL ;
    PORT
      LAYER M5 ;
        RECT 50.0640 164.0760 50.0880 164.1600 ;
    END
  END f_d[157]
  PIN f_d[158]
    DIRECTION INPUT ;
    USE SIGNAL ;
    PORT
      LAYER M5 ;
        RECT 50.3040 164.0760 50.3280 164.1600 ;
    END
  END f_d[158]
  PIN f_d[159]
    DIRECTION INPUT ;
    USE SIGNAL ;
    PORT
      LAYER M5 ;
        RECT 50.5440 164.0760 50.5680 164.1600 ;
    END
  END f_d[159]
  PIN f_d[160]
    DIRECTION INPUT ;
    USE SIGNAL ;
    PORT
      LAYER M5 ;
        RECT 50.7840 164.0760 50.8080 164.1600 ;
    END
  END f_d[160]
  PIN f_d[161]
    DIRECTION INPUT ;
    USE SIGNAL ;
    PORT
      LAYER M5 ;
        RECT 51.0240 164.0760 51.0480 164.1600 ;
    END
  END f_d[161]
  PIN f_d[162]
    DIRECTION INPUT ;
    USE SIGNAL ;
    PORT
      LAYER M5 ;
        RECT 51.2640 164.0760 51.2880 164.1600 ;
    END
  END f_d[162]
  PIN f_d[163]
    DIRECTION INPUT ;
    USE SIGNAL ;
    PORT
      LAYER M5 ;
        RECT 51.5040 164.0760 51.5280 164.1600 ;
    END
  END f_d[163]
  PIN f_d[164]
    DIRECTION INPUT ;
    USE SIGNAL ;
    PORT
      LAYER M5 ;
        RECT 51.7440 164.0760 51.7680 164.1600 ;
    END
  END f_d[164]
  PIN f_d[165]
    DIRECTION INPUT ;
    USE SIGNAL ;
    PORT
      LAYER M5 ;
        RECT 51.9840 164.0760 52.0080 164.1600 ;
    END
  END f_d[165]
  PIN f_d[166]
    DIRECTION INPUT ;
    USE SIGNAL ;
    PORT
      LAYER M5 ;
        RECT 52.2240 164.0760 52.2480 164.1600 ;
    END
  END f_d[166]
  PIN f_d[167]
    DIRECTION INPUT ;
    USE SIGNAL ;
    PORT
      LAYER M5 ;
        RECT 52.4640 164.0760 52.4880 164.1600 ;
    END
  END f_d[167]
  PIN f_d[168]
    DIRECTION INPUT ;
    USE SIGNAL ;
    PORT
      LAYER M5 ;
        RECT 52.7040 164.0760 52.7280 164.1600 ;
    END
  END f_d[168]
  PIN f_d[169]
    DIRECTION INPUT ;
    USE SIGNAL ;
    PORT
      LAYER M5 ;
        RECT 52.9440 164.0760 52.9680 164.1600 ;
    END
  END f_d[169]
  PIN f_d[170]
    DIRECTION INPUT ;
    USE SIGNAL ;
    PORT
      LAYER M5 ;
        RECT 53.1840 164.0760 53.2080 164.1600 ;
    END
  END f_d[170]
  PIN f_d[171]
    DIRECTION INPUT ;
    USE SIGNAL ;
    PORT
      LAYER M5 ;
        RECT 53.4240 164.0760 53.4480 164.1600 ;
    END
  END f_d[171]
  PIN f_d[172]
    DIRECTION INPUT ;
    USE SIGNAL ;
    PORT
      LAYER M5 ;
        RECT 53.6640 164.0760 53.6880 164.1600 ;
    END
  END f_d[172]
  PIN f_d[173]
    DIRECTION INPUT ;
    USE SIGNAL ;
    PORT
      LAYER M5 ;
        RECT 53.9040 164.0760 53.9280 164.1600 ;
    END
  END f_d[173]
  PIN f_d[174]
    DIRECTION INPUT ;
    USE SIGNAL ;
    PORT
      LAYER M5 ;
        RECT 54.1440 164.0760 54.1680 164.1600 ;
    END
  END f_d[174]
  PIN f_d[175]
    DIRECTION INPUT ;
    USE SIGNAL ;
    PORT
      LAYER M5 ;
        RECT 54.3840 164.0760 54.4080 164.1600 ;
    END
  END f_d[175]
  PIN f_d[176]
    DIRECTION INPUT ;
    USE SIGNAL ;
    PORT
      LAYER M5 ;
        RECT 54.6240 164.0760 54.6480 164.1600 ;
    END
  END f_d[176]
  PIN f_d[177]
    DIRECTION INPUT ;
    USE SIGNAL ;
    PORT
      LAYER M5 ;
        RECT 54.8640 164.0760 54.8880 164.1600 ;
    END
  END f_d[177]
  PIN f_d[178]
    DIRECTION INPUT ;
    USE SIGNAL ;
    PORT
      LAYER M5 ;
        RECT 55.1040 164.0760 55.1280 164.1600 ;
    END
  END f_d[178]
  PIN f_d[179]
    DIRECTION INPUT ;
    USE SIGNAL ;
    PORT
      LAYER M5 ;
        RECT 55.3440 164.0760 55.3680 164.1600 ;
    END
  END f_d[179]
  PIN f_d[180]
    DIRECTION INPUT ;
    USE SIGNAL ;
    PORT
      LAYER M5 ;
        RECT 55.5840 164.0760 55.6080 164.1600 ;
    END
  END f_d[180]
  PIN f_d[181]
    DIRECTION INPUT ;
    USE SIGNAL ;
    PORT
      LAYER M5 ;
        RECT 55.8240 164.0760 55.8480 164.1600 ;
    END
  END f_d[181]
  PIN f_d[182]
    DIRECTION INPUT ;
    USE SIGNAL ;
    PORT
      LAYER M5 ;
        RECT 56.0640 164.0760 56.0880 164.1600 ;
    END
  END f_d[182]
  PIN f_d[183]
    DIRECTION INPUT ;
    USE SIGNAL ;
    PORT
      LAYER M5 ;
        RECT 56.3040 164.0760 56.3280 164.1600 ;
    END
  END f_d[183]
  PIN f_d[184]
    DIRECTION INPUT ;
    USE SIGNAL ;
    PORT
      LAYER M5 ;
        RECT 56.5440 164.0760 56.5680 164.1600 ;
    END
  END f_d[184]
  PIN f_d[185]
    DIRECTION INPUT ;
    USE SIGNAL ;
    PORT
      LAYER M5 ;
        RECT 56.7840 164.0760 56.8080 164.1600 ;
    END
  END f_d[185]
  PIN f_d[186]
    DIRECTION INPUT ;
    USE SIGNAL ;
    PORT
      LAYER M5 ;
        RECT 57.0240 164.0760 57.0480 164.1600 ;
    END
  END f_d[186]
  PIN f_d[187]
    DIRECTION INPUT ;
    USE SIGNAL ;
    PORT
      LAYER M5 ;
        RECT 57.2640 164.0760 57.2880 164.1600 ;
    END
  END f_d[187]
  PIN f_d[188]
    DIRECTION INPUT ;
    USE SIGNAL ;
    PORT
      LAYER M5 ;
        RECT 57.5040 164.0760 57.5280 164.1600 ;
    END
  END f_d[188]
  PIN f_d[189]
    DIRECTION INPUT ;
    USE SIGNAL ;
    PORT
      LAYER M5 ;
        RECT 57.7440 164.0760 57.7680 164.1600 ;
    END
  END f_d[189]
  PIN f_d[190]
    DIRECTION INPUT ;
    USE SIGNAL ;
    PORT
      LAYER M5 ;
        RECT 57.9840 164.0760 58.0080 164.1600 ;
    END
  END f_d[190]
  PIN f_d[191]
    DIRECTION INPUT ;
    USE SIGNAL ;
    PORT
      LAYER M5 ;
        RECT 58.2240 164.0760 58.2480 164.1600 ;
    END
  END f_d[191]
  PIN f_d[192]
    DIRECTION INPUT ;
    USE SIGNAL ;
    PORT
      LAYER M5 ;
        RECT 58.4640 164.0760 58.4880 164.1600 ;
    END
  END f_d[192]
  PIN f_d[193]
    DIRECTION INPUT ;
    USE SIGNAL ;
    PORT
      LAYER M5 ;
        RECT 58.7040 164.0760 58.7280 164.1600 ;
    END
  END f_d[193]
  PIN f_d[194]
    DIRECTION INPUT ;
    USE SIGNAL ;
    PORT
      LAYER M5 ;
        RECT 58.9440 164.0760 58.9680 164.1600 ;
    END
  END f_d[194]
  PIN f_d[195]
    DIRECTION INPUT ;
    USE SIGNAL ;
    PORT
      LAYER M5 ;
        RECT 59.1840 164.0760 59.2080 164.1600 ;
    END
  END f_d[195]
  PIN f_d[196]
    DIRECTION INPUT ;
    USE SIGNAL ;
    PORT
      LAYER M5 ;
        RECT 59.4240 164.0760 59.4480 164.1600 ;
    END
  END f_d[196]
  PIN f_d[197]
    DIRECTION INPUT ;
    USE SIGNAL ;
    PORT
      LAYER M5 ;
        RECT 59.6640 164.0760 59.6880 164.1600 ;
    END
  END f_d[197]
  PIN f_d[198]
    DIRECTION INPUT ;
    USE SIGNAL ;
    PORT
      LAYER M5 ;
        RECT 59.9040 164.0760 59.9280 164.1600 ;
    END
  END f_d[198]
  PIN f_d[199]
    DIRECTION INPUT ;
    USE SIGNAL ;
    PORT
      LAYER M5 ;
        RECT 60.1440 164.0760 60.1680 164.1600 ;
    END
  END f_d[199]
  PIN f_d[200]
    DIRECTION INPUT ;
    USE SIGNAL ;
    PORT
      LAYER M5 ;
        RECT 60.3840 164.0760 60.4080 164.1600 ;
    END
  END f_d[200]
  PIN f_d[201]
    DIRECTION INPUT ;
    USE SIGNAL ;
    PORT
      LAYER M5 ;
        RECT 60.6240 164.0760 60.6480 164.1600 ;
    END
  END f_d[201]
  PIN f_d[202]
    DIRECTION INPUT ;
    USE SIGNAL ;
    PORT
      LAYER M5 ;
        RECT 60.8640 164.0760 60.8880 164.1600 ;
    END
  END f_d[202]
  PIN f_d[203]
    DIRECTION INPUT ;
    USE SIGNAL ;
    PORT
      LAYER M5 ;
        RECT 61.1040 164.0760 61.1280 164.1600 ;
    END
  END f_d[203]
  PIN f_d[204]
    DIRECTION INPUT ;
    USE SIGNAL ;
    PORT
      LAYER M5 ;
        RECT 61.3440 164.0760 61.3680 164.1600 ;
    END
  END f_d[204]
  PIN f_d[205]
    DIRECTION INPUT ;
    USE SIGNAL ;
    PORT
      LAYER M5 ;
        RECT 61.5840 164.0760 61.6080 164.1600 ;
    END
  END f_d[205]
  PIN f_d[206]
    DIRECTION INPUT ;
    USE SIGNAL ;
    PORT
      LAYER M5 ;
        RECT 61.8240 164.0760 61.8480 164.1600 ;
    END
  END f_d[206]
  PIN f_d[207]
    DIRECTION INPUT ;
    USE SIGNAL ;
    PORT
      LAYER M5 ;
        RECT 62.0640 164.0760 62.0880 164.1600 ;
    END
  END f_d[207]
  PIN f_d[208]
    DIRECTION INPUT ;
    USE SIGNAL ;
    PORT
      LAYER M5 ;
        RECT 62.3040 164.0760 62.3280 164.1600 ;
    END
  END f_d[208]
  PIN f_d[209]
    DIRECTION INPUT ;
    USE SIGNAL ;
    PORT
      LAYER M5 ;
        RECT 62.5440 164.0760 62.5680 164.1600 ;
    END
  END f_d[209]
  PIN f_d[210]
    DIRECTION INPUT ;
    USE SIGNAL ;
    PORT
      LAYER M5 ;
        RECT 62.7840 164.0760 62.8080 164.1600 ;
    END
  END f_d[210]
  PIN f_d[211]
    DIRECTION INPUT ;
    USE SIGNAL ;
    PORT
      LAYER M5 ;
        RECT 63.0240 164.0760 63.0480 164.1600 ;
    END
  END f_d[211]
  PIN f_d[212]
    DIRECTION INPUT ;
    USE SIGNAL ;
    PORT
      LAYER M5 ;
        RECT 63.2640 164.0760 63.2880 164.1600 ;
    END
  END f_d[212]
  PIN f_d[213]
    DIRECTION INPUT ;
    USE SIGNAL ;
    PORT
      LAYER M5 ;
        RECT 63.5040 164.0760 63.5280 164.1600 ;
    END
  END f_d[213]
  PIN f_d[214]
    DIRECTION INPUT ;
    USE SIGNAL ;
    PORT
      LAYER M5 ;
        RECT 63.7440 164.0760 63.7680 164.1600 ;
    END
  END f_d[214]
  PIN f_d[215]
    DIRECTION INPUT ;
    USE SIGNAL ;
    PORT
      LAYER M5 ;
        RECT 63.9840 164.0760 64.0080 164.1600 ;
    END
  END f_d[215]
  PIN f_d[216]
    DIRECTION INPUT ;
    USE SIGNAL ;
    PORT
      LAYER M5 ;
        RECT 64.2240 164.0760 64.2480 164.1600 ;
    END
  END f_d[216]
  PIN f_d[217]
    DIRECTION INPUT ;
    USE SIGNAL ;
    PORT
      LAYER M5 ;
        RECT 64.4640 164.0760 64.4880 164.1600 ;
    END
  END f_d[217]
  PIN f_d[218]
    DIRECTION INPUT ;
    USE SIGNAL ;
    PORT
      LAYER M5 ;
        RECT 64.7040 164.0760 64.7280 164.1600 ;
    END
  END f_d[218]
  PIN f_d[219]
    DIRECTION INPUT ;
    USE SIGNAL ;
    PORT
      LAYER M5 ;
        RECT 64.9440 164.0760 64.9680 164.1600 ;
    END
  END f_d[219]
  PIN f_d[220]
    DIRECTION INPUT ;
    USE SIGNAL ;
    PORT
      LAYER M5 ;
        RECT 65.1840 164.0760 65.2080 164.1600 ;
    END
  END f_d[220]
  PIN f_d[221]
    DIRECTION INPUT ;
    USE SIGNAL ;
    PORT
      LAYER M5 ;
        RECT 65.4240 164.0760 65.4480 164.1600 ;
    END
  END f_d[221]
  PIN f_d[222]
    DIRECTION INPUT ;
    USE SIGNAL ;
    PORT
      LAYER M5 ;
        RECT 65.6160 164.0760 65.6400 164.1600 ;
    END
  END f_d[222]
  PIN f_d[223]
    DIRECTION INPUT ;
    USE SIGNAL ;
    PORT
      LAYER M5 ;
        RECT 65.8560 164.0760 65.8800 164.1600 ;
    END
  END f_d[223]
  PIN f_d[224]
    DIRECTION INPUT ;
    USE SIGNAL ;
    PORT
      LAYER M5 ;
        RECT 66.0960 164.0760 66.1200 164.1600 ;
    END
  END f_d[224]
  PIN f_d[225]
    DIRECTION INPUT ;
    USE SIGNAL ;
    PORT
      LAYER M5 ;
        RECT 66.3360 164.0760 66.3600 164.1600 ;
    END
  END f_d[225]
  PIN f_d[226]
    DIRECTION INPUT ;
    USE SIGNAL ;
    PORT
      LAYER M5 ;
        RECT 66.5760 164.0760 66.6000 164.1600 ;
    END
  END f_d[226]
  PIN f_d[227]
    DIRECTION INPUT ;
    USE SIGNAL ;
    PORT
      LAYER M5 ;
        RECT 66.8160 164.0760 66.8400 164.1600 ;
    END
  END f_d[227]
  PIN f_d[228]
    DIRECTION INPUT ;
    USE SIGNAL ;
    PORT
      LAYER M5 ;
        RECT 67.0560 164.0760 67.0800 164.1600 ;
    END
  END f_d[228]
  PIN f_d[229]
    DIRECTION INPUT ;
    USE SIGNAL ;
    PORT
      LAYER M5 ;
        RECT 67.2960 164.0760 67.3200 164.1600 ;
    END
  END f_d[229]
  PIN f_d[230]
    DIRECTION INPUT ;
    USE SIGNAL ;
    PORT
      LAYER M5 ;
        RECT 67.5360 164.0760 67.5600 164.1600 ;
    END
  END f_d[230]
  PIN f_d[231]
    DIRECTION INPUT ;
    USE SIGNAL ;
    PORT
      LAYER M5 ;
        RECT 67.7760 164.0760 67.8000 164.1600 ;
    END
  END f_d[231]
  PIN f_d[232]
    DIRECTION INPUT ;
    USE SIGNAL ;
    PORT
      LAYER M5 ;
        RECT 68.0160 164.0760 68.0400 164.1600 ;
    END
  END f_d[232]
  PIN f_d[233]
    DIRECTION INPUT ;
    USE SIGNAL ;
    PORT
      LAYER M5 ;
        RECT 68.2560 164.0760 68.2800 164.1600 ;
    END
  END f_d[233]
  PIN f_d[234]
    DIRECTION INPUT ;
    USE SIGNAL ;
    PORT
      LAYER M5 ;
        RECT 68.4960 164.0760 68.5200 164.1600 ;
    END
  END f_d[234]
  PIN f_d[235]
    DIRECTION INPUT ;
    USE SIGNAL ;
    PORT
      LAYER M5 ;
        RECT 68.7360 164.0760 68.7600 164.1600 ;
    END
  END f_d[235]
  PIN f_d[236]
    DIRECTION INPUT ;
    USE SIGNAL ;
    PORT
      LAYER M5 ;
        RECT 68.9760 164.0760 69.0000 164.1600 ;
    END
  END f_d[236]
  PIN f_d[237]
    DIRECTION INPUT ;
    USE SIGNAL ;
    PORT
      LAYER M5 ;
        RECT 69.2160 164.0760 69.2400 164.1600 ;
    END
  END f_d[237]
  PIN f_d[238]
    DIRECTION INPUT ;
    USE SIGNAL ;
    PORT
      LAYER M5 ;
        RECT 69.4560 164.0760 69.4800 164.1600 ;
    END
  END f_d[238]
  PIN f_d[239]
    DIRECTION INPUT ;
    USE SIGNAL ;
    PORT
      LAYER M5 ;
        RECT 69.6960 164.0760 69.7200 164.1600 ;
    END
  END f_d[239]
  PIN clk
    DIRECTION INPUT ;
    USE SIGNAL ;
    PORT
      LAYER M5 ;
        RECT 69.9360 164.0760 69.9600 164.1600 ;
    END
  END clk
  PIN rst_n
    DIRECTION INPUT ;
    USE SIGNAL ;
    PORT
      LAYER M5 ;
        RECT 70.1760 164.0760 70.2000 164.1600 ;
    END
  END rst_n
  PIN f_d[240]
    DIRECTION INPUT ;
    USE SIGNAL ;
    PORT
      LAYER M5 ;
        RECT 70.4160 164.0760 70.4400 164.1600 ;
    END
  END f_d[240]
  PIN f_d[241]
    DIRECTION INPUT ;
    USE SIGNAL ;
    PORT
      LAYER M5 ;
        RECT 70.6560 164.0760 70.6800 164.1600 ;
    END
  END f_d[241]
  PIN f_d[242]
    DIRECTION INPUT ;
    USE SIGNAL ;
    PORT
      LAYER M5 ;
        RECT 70.8960 164.0760 70.9200 164.1600 ;
    END
  END f_d[242]
  PIN f_d[243]
    DIRECTION INPUT ;
    USE SIGNAL ;
    PORT
      LAYER M5 ;
        RECT 71.1360 164.0760 71.1600 164.1600 ;
    END
  END f_d[243]
  PIN f_d[244]
    DIRECTION INPUT ;
    USE SIGNAL ;
    PORT
      LAYER M5 ;
        RECT 71.3760 164.0760 71.4000 164.1600 ;
    END
  END f_d[244]
  PIN f_d[245]
    DIRECTION INPUT ;
    USE SIGNAL ;
    PORT
      LAYER M5 ;
        RECT 71.6160 164.0760 71.6400 164.1600 ;
    END
  END f_d[245]
  PIN f_d[246]
    DIRECTION INPUT ;
    USE SIGNAL ;
    PORT
      LAYER M5 ;
        RECT 71.8560 164.0760 71.8800 164.1600 ;
    END
  END f_d[246]
  PIN f_d[247]
    DIRECTION INPUT ;
    USE SIGNAL ;
    PORT
      LAYER M5 ;
        RECT 72.0960 164.0760 72.1200 164.1600 ;
    END
  END f_d[247]
  PIN f_d[248]
    DIRECTION INPUT ;
    USE SIGNAL ;
    PORT
      LAYER M5 ;
        RECT 72.3360 164.0760 72.3600 164.1600 ;
    END
  END f_d[248]
  PIN f_d[249]
    DIRECTION INPUT ;
    USE SIGNAL ;
    PORT
      LAYER M5 ;
        RECT 72.5760 164.0760 72.6000 164.1600 ;
    END
  END f_d[249]
  PIN f_d[250]
    DIRECTION INPUT ;
    USE SIGNAL ;
    PORT
      LAYER M5 ;
        RECT 72.8160 164.0760 72.8400 164.1600 ;
    END
  END f_d[250]
  PIN f_d[251]
    DIRECTION INPUT ;
    USE SIGNAL ;
    PORT
      LAYER M5 ;
        RECT 73.0560 164.0760 73.0800 164.1600 ;
    END
  END f_d[251]
  PIN f_d[252]
    DIRECTION INPUT ;
    USE SIGNAL ;
    PORT
      LAYER M5 ;
        RECT 73.2960 164.0760 73.3200 164.1600 ;
    END
  END f_d[252]
  PIN f_d[253]
    DIRECTION INPUT ;
    USE SIGNAL ;
    PORT
      LAYER M5 ;
        RECT 73.5360 164.0760 73.5600 164.1600 ;
    END
  END f_d[253]
  PIN f_d[254]
    DIRECTION INPUT ;
    USE SIGNAL ;
    PORT
      LAYER M5 ;
        RECT 73.7760 164.0760 73.8000 164.1600 ;
    END
  END f_d[254]
  PIN f_d[255]
    DIRECTION INPUT ;
    USE SIGNAL ;
    PORT
      LAYER M5 ;
        RECT 74.0160 164.0760 74.0400 164.1600 ;
    END
  END f_d[255]
  PIN f_d[256]
    DIRECTION INPUT ;
    USE SIGNAL ;
    PORT
      LAYER M5 ;
        RECT 74.2560 164.0760 74.2800 164.1600 ;
    END
  END f_d[256]
  PIN f_d[257]
    DIRECTION INPUT ;
    USE SIGNAL ;
    PORT
      LAYER M5 ;
        RECT 74.4960 164.0760 74.5200 164.1600 ;
    END
  END f_d[257]
  PIN f_d[258]
    DIRECTION INPUT ;
    USE SIGNAL ;
    PORT
      LAYER M5 ;
        RECT 74.7360 164.0760 74.7600 164.1600 ;
    END
  END f_d[258]
  PIN f_d[259]
    DIRECTION INPUT ;
    USE SIGNAL ;
    PORT
      LAYER M5 ;
        RECT 74.9760 164.0760 75.0000 164.1600 ;
    END
  END f_d[259]
  PIN f_d[260]
    DIRECTION INPUT ;
    USE SIGNAL ;
    PORT
      LAYER M5 ;
        RECT 75.2160 164.0760 75.2400 164.1600 ;
    END
  END f_d[260]
  PIN f_d[261]
    DIRECTION INPUT ;
    USE SIGNAL ;
    PORT
      LAYER M5 ;
        RECT 75.4560 164.0760 75.4800 164.1600 ;
    END
  END f_d[261]
  PIN f_d[262]
    DIRECTION INPUT ;
    USE SIGNAL ;
    PORT
      LAYER M5 ;
        RECT 75.6960 164.0760 75.7200 164.1600 ;
    END
  END f_d[262]
  PIN f_d[263]
    DIRECTION INPUT ;
    USE SIGNAL ;
    PORT
      LAYER M5 ;
        RECT 75.9360 164.0760 75.9600 164.1600 ;
    END
  END f_d[263]
  PIN f_d[264]
    DIRECTION INPUT ;
    USE SIGNAL ;
    PORT
      LAYER M5 ;
        RECT 76.1760 164.0760 76.2000 164.1600 ;
    END
  END f_d[264]
  PIN f_d[265]
    DIRECTION INPUT ;
    USE SIGNAL ;
    PORT
      LAYER M5 ;
        RECT 76.4160 164.0760 76.4400 164.1600 ;
    END
  END f_d[265]
  PIN f_d[266]
    DIRECTION INPUT ;
    USE SIGNAL ;
    PORT
      LAYER M5 ;
        RECT 76.6560 164.0760 76.6800 164.1600 ;
    END
  END f_d[266]
  PIN f_d[267]
    DIRECTION INPUT ;
    USE SIGNAL ;
    PORT
      LAYER M5 ;
        RECT 76.8960 164.0760 76.9200 164.1600 ;
    END
  END f_d[267]
  PIN f_d[268]
    DIRECTION INPUT ;
    USE SIGNAL ;
    PORT
      LAYER M5 ;
        RECT 77.1360 164.0760 77.1600 164.1600 ;
    END
  END f_d[268]
  PIN f_d[269]
    DIRECTION INPUT ;
    USE SIGNAL ;
    PORT
      LAYER M5 ;
        RECT 77.3760 164.0760 77.4000 164.1600 ;
    END
  END f_d[269]
  PIN f_d[270]
    DIRECTION INPUT ;
    USE SIGNAL ;
    PORT
      LAYER M5 ;
        RECT 77.6160 164.0760 77.6400 164.1600 ;
    END
  END f_d[270]
  PIN f_d[271]
    DIRECTION INPUT ;
    USE SIGNAL ;
    PORT
      LAYER M5 ;
        RECT 77.8560 164.0760 77.8800 164.1600 ;
    END
  END f_d[271]
  PIN f_d[272]
    DIRECTION INPUT ;
    USE SIGNAL ;
    PORT
      LAYER M5 ;
        RECT 78.0960 164.0760 78.1200 164.1600 ;
    END
  END f_d[272]
  PIN f_d[273]
    DIRECTION INPUT ;
    USE SIGNAL ;
    PORT
      LAYER M5 ;
        RECT 78.3360 164.0760 78.3600 164.1600 ;
    END
  END f_d[273]
  PIN f_d[274]
    DIRECTION INPUT ;
    USE SIGNAL ;
    PORT
      LAYER M5 ;
        RECT 78.5760 164.0760 78.6000 164.1600 ;
    END
  END f_d[274]
  PIN f_d[275]
    DIRECTION INPUT ;
    USE SIGNAL ;
    PORT
      LAYER M5 ;
        RECT 78.8160 164.0760 78.8400 164.1600 ;
    END
  END f_d[275]
  PIN f_d[276]
    DIRECTION INPUT ;
    USE SIGNAL ;
    PORT
      LAYER M5 ;
        RECT 79.0560 164.0760 79.0800 164.1600 ;
    END
  END f_d[276]
  PIN f_d[277]
    DIRECTION INPUT ;
    USE SIGNAL ;
    PORT
      LAYER M5 ;
        RECT 79.2960 164.0760 79.3200 164.1600 ;
    END
  END f_d[277]
  PIN f_d[278]
    DIRECTION INPUT ;
    USE SIGNAL ;
    PORT
      LAYER M5 ;
        RECT 79.5360 164.0760 79.5600 164.1600 ;
    END
  END f_d[278]
  PIN f_d[279]
    DIRECTION INPUT ;
    USE SIGNAL ;
    PORT
      LAYER M5 ;
        RECT 79.7760 164.0760 79.8000 164.1600 ;
    END
  END f_d[279]
  PIN f_d[280]
    DIRECTION INPUT ;
    USE SIGNAL ;
    PORT
      LAYER M5 ;
        RECT 80.0160 164.0760 80.0400 164.1600 ;
    END
  END f_d[280]
  PIN f_d[281]
    DIRECTION INPUT ;
    USE SIGNAL ;
    PORT
      LAYER M5 ;
        RECT 80.2560 164.0760 80.2800 164.1600 ;
    END
  END f_d[281]
  PIN f_d[282]
    DIRECTION INPUT ;
    USE SIGNAL ;
    PORT
      LAYER M5 ;
        RECT 80.4960 164.0760 80.5200 164.1600 ;
    END
  END f_d[282]
  PIN f_d[283]
    DIRECTION INPUT ;
    USE SIGNAL ;
    PORT
      LAYER M5 ;
        RECT 80.7360 164.0760 80.7600 164.1600 ;
    END
  END f_d[283]
  PIN f_d[284]
    DIRECTION INPUT ;
    USE SIGNAL ;
    PORT
      LAYER M5 ;
        RECT 80.9760 164.0760 81.0000 164.1600 ;
    END
  END f_d[284]
  PIN f_d[285]
    DIRECTION INPUT ;
    USE SIGNAL ;
    PORT
      LAYER M5 ;
        RECT 81.2160 164.0760 81.2400 164.1600 ;
    END
  END f_d[285]
  PIN f_d[286]
    DIRECTION INPUT ;
    USE SIGNAL ;
    PORT
      LAYER M5 ;
        RECT 81.4560 164.0760 81.4800 164.1600 ;
    END
  END f_d[286]
  PIN f_d[287]
    DIRECTION INPUT ;
    USE SIGNAL ;
    PORT
      LAYER M5 ;
        RECT 81.6960 164.0760 81.7200 164.1600 ;
    END
  END f_d[287]
  PIN f_d[288]
    DIRECTION INPUT ;
    USE SIGNAL ;
    PORT
      LAYER M5 ;
        RECT 81.9360 164.0760 81.9600 164.1600 ;
    END
  END f_d[288]
  PIN f_d[289]
    DIRECTION INPUT ;
    USE SIGNAL ;
    PORT
      LAYER M5 ;
        RECT 82.1760 164.0760 82.2000 164.1600 ;
    END
  END f_d[289]
  PIN f_d[290]
    DIRECTION INPUT ;
    USE SIGNAL ;
    PORT
      LAYER M5 ;
        RECT 82.4160 164.0760 82.4400 164.1600 ;
    END
  END f_d[290]
  PIN f_d[291]
    DIRECTION INPUT ;
    USE SIGNAL ;
    PORT
      LAYER M5 ;
        RECT 82.6560 164.0760 82.6800 164.1600 ;
    END
  END f_d[291]
  PIN f_d[292]
    DIRECTION INPUT ;
    USE SIGNAL ;
    PORT
      LAYER M5 ;
        RECT 82.8960 164.0760 82.9200 164.1600 ;
    END
  END f_d[292]
  PIN f_d[293]
    DIRECTION INPUT ;
    USE SIGNAL ;
    PORT
      LAYER M5 ;
        RECT 83.1360 164.0760 83.1600 164.1600 ;
    END
  END f_d[293]
  PIN f_d[294]
    DIRECTION INPUT ;
    USE SIGNAL ;
    PORT
      LAYER M5 ;
        RECT 83.3760 164.0760 83.4000 164.1600 ;
    END
  END f_d[294]
  PIN f_d[295]
    DIRECTION INPUT ;
    USE SIGNAL ;
    PORT
      LAYER M5 ;
        RECT 83.6160 164.0760 83.6400 164.1600 ;
    END
  END f_d[295]
  PIN f_d[296]
    DIRECTION INPUT ;
    USE SIGNAL ;
    PORT
      LAYER M5 ;
        RECT 83.8560 164.0760 83.8800 164.1600 ;
    END
  END f_d[296]
  PIN f_d[297]
    DIRECTION INPUT ;
    USE SIGNAL ;
    PORT
      LAYER M5 ;
        RECT 84.0960 164.0760 84.1200 164.1600 ;
    END
  END f_d[297]
  PIN f_d[298]
    DIRECTION INPUT ;
    USE SIGNAL ;
    PORT
      LAYER M5 ;
        RECT 84.3360 164.0760 84.3600 164.1600 ;
    END
  END f_d[298]
  PIN f_d[299]
    DIRECTION INPUT ;
    USE SIGNAL ;
    PORT
      LAYER M5 ;
        RECT 84.5760 164.0760 84.6000 164.1600 ;
    END
  END f_d[299]
  PIN f_d[300]
    DIRECTION INPUT ;
    USE SIGNAL ;
    PORT
      LAYER M5 ;
        RECT 84.8160 164.0760 84.8400 164.1600 ;
    END
  END f_d[300]
  PIN f_d[301]
    DIRECTION INPUT ;
    USE SIGNAL ;
    PORT
      LAYER M5 ;
        RECT 85.0560 164.0760 85.0800 164.1600 ;
    END
  END f_d[301]
  PIN f_d[302]
    DIRECTION INPUT ;
    USE SIGNAL ;
    PORT
      LAYER M5 ;
        RECT 85.2960 164.0760 85.3200 164.1600 ;
    END
  END f_d[302]
  PIN f_d[303]
    DIRECTION INPUT ;
    USE SIGNAL ;
    PORT
      LAYER M5 ;
        RECT 85.5360 164.0760 85.5600 164.1600 ;
    END
  END f_d[303]
  PIN f_d[304]
    DIRECTION INPUT ;
    USE SIGNAL ;
    PORT
      LAYER M5 ;
        RECT 85.7760 164.0760 85.8000 164.1600 ;
    END
  END f_d[304]
  PIN f_d[305]
    DIRECTION INPUT ;
    USE SIGNAL ;
    PORT
      LAYER M5 ;
        RECT 86.0160 164.0760 86.0400 164.1600 ;
    END
  END f_d[305]
  PIN f_d[306]
    DIRECTION INPUT ;
    USE SIGNAL ;
    PORT
      LAYER M5 ;
        RECT 86.2560 164.0760 86.2800 164.1600 ;
    END
  END f_d[306]
  PIN f_d[307]
    DIRECTION INPUT ;
    USE SIGNAL ;
    PORT
      LAYER M5 ;
        RECT 86.4960 164.0760 86.5200 164.1600 ;
    END
  END f_d[307]
  PIN f_d[308]
    DIRECTION INPUT ;
    USE SIGNAL ;
    PORT
      LAYER M5 ;
        RECT 86.7360 164.0760 86.7600 164.1600 ;
    END
  END f_d[308]
  PIN f_d[309]
    DIRECTION INPUT ;
    USE SIGNAL ;
    PORT
      LAYER M5 ;
        RECT 86.9760 164.0760 87.0000 164.1600 ;
    END
  END f_d[309]
  PIN f_d[310]
    DIRECTION INPUT ;
    USE SIGNAL ;
    PORT
      LAYER M5 ;
        RECT 87.2160 164.0760 87.2400 164.1600 ;
    END
  END f_d[310]
  PIN f_d[311]
    DIRECTION INPUT ;
    USE SIGNAL ;
    PORT
      LAYER M5 ;
        RECT 87.4560 164.0760 87.4800 164.1600 ;
    END
  END f_d[311]
  PIN f_d[312]
    DIRECTION INPUT ;
    USE SIGNAL ;
    PORT
      LAYER M5 ;
        RECT 87.6960 164.0760 87.7200 164.1600 ;
    END
  END f_d[312]
  PIN f_d[313]
    DIRECTION INPUT ;
    USE SIGNAL ;
    PORT
      LAYER M5 ;
        RECT 87.9360 164.0760 87.9600 164.1600 ;
    END
  END f_d[313]
  PIN f_d[314]
    DIRECTION INPUT ;
    USE SIGNAL ;
    PORT
      LAYER M5 ;
        RECT 88.1760 164.0760 88.2000 164.1600 ;
    END
  END f_d[314]
  PIN f_d[315]
    DIRECTION INPUT ;
    USE SIGNAL ;
    PORT
      LAYER M5 ;
        RECT 88.4160 164.0760 88.4400 164.1600 ;
    END
  END f_d[315]
  PIN f_d[316]
    DIRECTION INPUT ;
    USE SIGNAL ;
    PORT
      LAYER M5 ;
        RECT 88.6560 164.0760 88.6800 164.1600 ;
    END
  END f_d[316]
  PIN f_d[317]
    DIRECTION INPUT ;
    USE SIGNAL ;
    PORT
      LAYER M5 ;
        RECT 88.8960 164.0760 88.9200 164.1600 ;
    END
  END f_d[317]
  PIN f_d[318]
    DIRECTION INPUT ;
    USE SIGNAL ;
    PORT
      LAYER M5 ;
        RECT 89.1360 164.0760 89.1600 164.1600 ;
    END
  END f_d[318]
  PIN f_d[319]
    DIRECTION INPUT ;
    USE SIGNAL ;
    PORT
      LAYER M5 ;
        RECT 89.3760 164.0760 89.4000 164.1600 ;
    END
  END f_d[319]
  PIN f_d[320]
    DIRECTION INPUT ;
    USE SIGNAL ;
    PORT
      LAYER M5 ;
        RECT 89.6160 164.0760 89.6400 164.1600 ;
    END
  END f_d[320]
  PIN f_d[321]
    DIRECTION INPUT ;
    USE SIGNAL ;
    PORT
      LAYER M5 ;
        RECT 89.8560 164.0760 89.8800 164.1600 ;
    END
  END f_d[321]
  PIN f_d[322]
    DIRECTION INPUT ;
    USE SIGNAL ;
    PORT
      LAYER M5 ;
        RECT 90.0480 164.0760 90.0720 164.1600 ;
    END
  END f_d[322]
  PIN f_d[323]
    DIRECTION INPUT ;
    USE SIGNAL ;
    PORT
      LAYER M5 ;
        RECT 90.2880 164.0760 90.3120 164.1600 ;
    END
  END f_d[323]
  PIN f_d[324]
    DIRECTION INPUT ;
    USE SIGNAL ;
    PORT
      LAYER M5 ;
        RECT 90.5280 164.0760 90.5520 164.1600 ;
    END
  END f_d[324]
  PIN f_d[325]
    DIRECTION INPUT ;
    USE SIGNAL ;
    PORT
      LAYER M5 ;
        RECT 90.7680 164.0760 90.7920 164.1600 ;
    END
  END f_d[325]
  PIN f_d[326]
    DIRECTION INPUT ;
    USE SIGNAL ;
    PORT
      LAYER M5 ;
        RECT 91.0080 164.0760 91.0320 164.1600 ;
    END
  END f_d[326]
  PIN f_d[327]
    DIRECTION INPUT ;
    USE SIGNAL ;
    PORT
      LAYER M5 ;
        RECT 91.2480 164.0760 91.2720 164.1600 ;
    END
  END f_d[327]
  PIN f_d[328]
    DIRECTION INPUT ;
    USE SIGNAL ;
    PORT
      LAYER M5 ;
        RECT 91.4880 164.0760 91.5120 164.1600 ;
    END
  END f_d[328]
  PIN f_d[329]
    DIRECTION INPUT ;
    USE SIGNAL ;
    PORT
      LAYER M5 ;
        RECT 91.7280 164.0760 91.7520 164.1600 ;
    END
  END f_d[329]
  PIN f_d[330]
    DIRECTION INPUT ;
    USE SIGNAL ;
    PORT
      LAYER M5 ;
        RECT 91.9680 164.0760 91.9920 164.1600 ;
    END
  END f_d[330]
  PIN f_d[331]
    DIRECTION INPUT ;
    USE SIGNAL ;
    PORT
      LAYER M5 ;
        RECT 92.2080 164.0760 92.2320 164.1600 ;
    END
  END f_d[331]
  PIN f_d[332]
    DIRECTION INPUT ;
    USE SIGNAL ;
    PORT
      LAYER M5 ;
        RECT 92.4480 164.0760 92.4720 164.1600 ;
    END
  END f_d[332]
  PIN f_d[333]
    DIRECTION INPUT ;
    USE SIGNAL ;
    PORT
      LAYER M5 ;
        RECT 92.6880 164.0760 92.7120 164.1600 ;
    END
  END f_d[333]
  PIN f_d[334]
    DIRECTION INPUT ;
    USE SIGNAL ;
    PORT
      LAYER M5 ;
        RECT 92.9280 164.0760 92.9520 164.1600 ;
    END
  END f_d[334]
  PIN f_d[335]
    DIRECTION INPUT ;
    USE SIGNAL ;
    PORT
      LAYER M5 ;
        RECT 93.1680 164.0760 93.1920 164.1600 ;
    END
  END f_d[335]
  PIN f_d[336]
    DIRECTION INPUT ;
    USE SIGNAL ;
    PORT
      LAYER M5 ;
        RECT 93.4080 164.0760 93.4320 164.1600 ;
    END
  END f_d[336]
  PIN f_d[337]
    DIRECTION INPUT ;
    USE SIGNAL ;
    PORT
      LAYER M5 ;
        RECT 93.6480 164.0760 93.6720 164.1600 ;
    END
  END f_d[337]
  PIN f_d[338]
    DIRECTION INPUT ;
    USE SIGNAL ;
    PORT
      LAYER M5 ;
        RECT 93.8880 164.0760 93.9120 164.1600 ;
    END
  END f_d[338]
  PIN f_d[339]
    DIRECTION INPUT ;
    USE SIGNAL ;
    PORT
      LAYER M5 ;
        RECT 94.1280 164.0760 94.1520 164.1600 ;
    END
  END f_d[339]
  PIN f_d[340]
    DIRECTION INPUT ;
    USE SIGNAL ;
    PORT
      LAYER M5 ;
        RECT 94.3680 164.0760 94.3920 164.1600 ;
    END
  END f_d[340]
  PIN f_d[341]
    DIRECTION INPUT ;
    USE SIGNAL ;
    PORT
      LAYER M5 ;
        RECT 94.6080 164.0760 94.6320 164.1600 ;
    END
  END f_d[341]
  PIN f_d[342]
    DIRECTION INPUT ;
    USE SIGNAL ;
    PORT
      LAYER M5 ;
        RECT 94.8480 164.0760 94.8720 164.1600 ;
    END
  END f_d[342]
  PIN f_d[343]
    DIRECTION INPUT ;
    USE SIGNAL ;
    PORT
      LAYER M5 ;
        RECT 95.0880 164.0760 95.1120 164.1600 ;
    END
  END f_d[343]
  PIN f_d[344]
    DIRECTION INPUT ;
    USE SIGNAL ;
    PORT
      LAYER M5 ;
        RECT 95.3280 164.0760 95.3520 164.1600 ;
    END
  END f_d[344]
  PIN f_d[345]
    DIRECTION INPUT ;
    USE SIGNAL ;
    PORT
      LAYER M5 ;
        RECT 95.5680 164.0760 95.5920 164.1600 ;
    END
  END f_d[345]
  PIN f_d[346]
    DIRECTION INPUT ;
    USE SIGNAL ;
    PORT
      LAYER M5 ;
        RECT 95.8080 164.0760 95.8320 164.1600 ;
    END
  END f_d[346]
  PIN f_d[347]
    DIRECTION INPUT ;
    USE SIGNAL ;
    PORT
      LAYER M5 ;
        RECT 96.0480 164.0760 96.0720 164.1600 ;
    END
  END f_d[347]
  PIN f_d[348]
    DIRECTION INPUT ;
    USE SIGNAL ;
    PORT
      LAYER M5 ;
        RECT 96.2880 164.0760 96.3120 164.1600 ;
    END
  END f_d[348]
  PIN f_d[349]
    DIRECTION INPUT ;
    USE SIGNAL ;
    PORT
      LAYER M5 ;
        RECT 96.5280 164.0760 96.5520 164.1600 ;
    END
  END f_d[349]
  PIN f_d[350]
    DIRECTION INPUT ;
    USE SIGNAL ;
    PORT
      LAYER M5 ;
        RECT 96.7680 164.0760 96.7920 164.1600 ;
    END
  END f_d[350]
  PIN f_d[351]
    DIRECTION INPUT ;
    USE SIGNAL ;
    PORT
      LAYER M5 ;
        RECT 97.0080 164.0760 97.0320 164.1600 ;
    END
  END f_d[351]
  PIN f_d[352]
    DIRECTION INPUT ;
    USE SIGNAL ;
    PORT
      LAYER M5 ;
        RECT 97.2480 164.0760 97.2720 164.1600 ;
    END
  END f_d[352]
  PIN f_d[353]
    DIRECTION INPUT ;
    USE SIGNAL ;
    PORT
      LAYER M5 ;
        RECT 97.4880 164.0760 97.5120 164.1600 ;
    END
  END f_d[353]
  PIN f_d[354]
    DIRECTION INPUT ;
    USE SIGNAL ;
    PORT
      LAYER M5 ;
        RECT 97.7280 164.0760 97.7520 164.1600 ;
    END
  END f_d[354]
  PIN f_d[355]
    DIRECTION INPUT ;
    USE SIGNAL ;
    PORT
      LAYER M5 ;
        RECT 97.9680 164.0760 97.9920 164.1600 ;
    END
  END f_d[355]
  PIN f_d[356]
    DIRECTION INPUT ;
    USE SIGNAL ;
    PORT
      LAYER M5 ;
        RECT 98.2080 164.0760 98.2320 164.1600 ;
    END
  END f_d[356]
  PIN f_d[357]
    DIRECTION INPUT ;
    USE SIGNAL ;
    PORT
      LAYER M5 ;
        RECT 98.4480 164.0760 98.4720 164.1600 ;
    END
  END f_d[357]
  PIN f_d[358]
    DIRECTION INPUT ;
    USE SIGNAL ;
    PORT
      LAYER M5 ;
        RECT 98.6880 164.0760 98.7120 164.1600 ;
    END
  END f_d[358]
  PIN f_d[359]
    DIRECTION INPUT ;
    USE SIGNAL ;
    PORT
      LAYER M5 ;
        RECT 98.9280 164.0760 98.9520 164.1600 ;
    END
  END f_d[359]
  PIN f_d[360]
    DIRECTION INPUT ;
    USE SIGNAL ;
    PORT
      LAYER M5 ;
        RECT 99.1680 164.0760 99.1920 164.1600 ;
    END
  END f_d[360]
  PIN f_d[361]
    DIRECTION INPUT ;
    USE SIGNAL ;
    PORT
      LAYER M5 ;
        RECT 99.4080 164.0760 99.4320 164.1600 ;
    END
  END f_d[361]
  PIN f_d[362]
    DIRECTION INPUT ;
    USE SIGNAL ;
    PORT
      LAYER M5 ;
        RECT 99.6480 164.0760 99.6720 164.1600 ;
    END
  END f_d[362]
  PIN f_d[363]
    DIRECTION INPUT ;
    USE SIGNAL ;
    PORT
      LAYER M5 ;
        RECT 99.8880 164.0760 99.9120 164.1600 ;
    END
  END f_d[363]
  PIN f_d[364]
    DIRECTION INPUT ;
    USE SIGNAL ;
    PORT
      LAYER M5 ;
        RECT 100.1280 164.0760 100.1520 164.1600 ;
    END
  END f_d[364]
  PIN f_d[365]
    DIRECTION INPUT ;
    USE SIGNAL ;
    PORT
      LAYER M5 ;
        RECT 100.3680 164.0760 100.3920 164.1600 ;
    END
  END f_d[365]
  PIN f_d[366]
    DIRECTION INPUT ;
    USE SIGNAL ;
    PORT
      LAYER M5 ;
        RECT 100.6080 164.0760 100.6320 164.1600 ;
    END
  END f_d[366]
  PIN f_d[367]
    DIRECTION INPUT ;
    USE SIGNAL ;
    PORT
      LAYER M5 ;
        RECT 100.8480 164.0760 100.8720 164.1600 ;
    END
  END f_d[367]
  PIN f_d[368]
    DIRECTION INPUT ;
    USE SIGNAL ;
    PORT
      LAYER M5 ;
        RECT 101.0880 164.0760 101.1120 164.1600 ;
    END
  END f_d[368]
  PIN f_d[369]
    DIRECTION INPUT ;
    USE SIGNAL ;
    PORT
      LAYER M5 ;
        RECT 101.3280 164.0760 101.3520 164.1600 ;
    END
  END f_d[369]
  PIN f_d[370]
    DIRECTION INPUT ;
    USE SIGNAL ;
    PORT
      LAYER M5 ;
        RECT 101.5680 164.0760 101.5920 164.1600 ;
    END
  END f_d[370]
  PIN f_d[371]
    DIRECTION INPUT ;
    USE SIGNAL ;
    PORT
      LAYER M5 ;
        RECT 101.8080 164.0760 101.8320 164.1600 ;
    END
  END f_d[371]
  PIN f_d[372]
    DIRECTION INPUT ;
    USE SIGNAL ;
    PORT
      LAYER M5 ;
        RECT 102.0480 164.0760 102.0720 164.1600 ;
    END
  END f_d[372]
  PIN f_d[373]
    DIRECTION INPUT ;
    USE SIGNAL ;
    PORT
      LAYER M5 ;
        RECT 102.2880 164.0760 102.3120 164.1600 ;
    END
  END f_d[373]
  PIN f_d[374]
    DIRECTION INPUT ;
    USE SIGNAL ;
    PORT
      LAYER M5 ;
        RECT 102.5280 164.0760 102.5520 164.1600 ;
    END
  END f_d[374]
  PIN f_d[375]
    DIRECTION INPUT ;
    USE SIGNAL ;
    PORT
      LAYER M5 ;
        RECT 102.7680 164.0760 102.7920 164.1600 ;
    END
  END f_d[375]
  PIN f_d[376]
    DIRECTION INPUT ;
    USE SIGNAL ;
    PORT
      LAYER M5 ;
        RECT 103.0080 164.0760 103.0320 164.1600 ;
    END
  END f_d[376]
  PIN f_d[377]
    DIRECTION INPUT ;
    USE SIGNAL ;
    PORT
      LAYER M5 ;
        RECT 103.2480 164.0760 103.2720 164.1600 ;
    END
  END f_d[377]
  PIN f_d[378]
    DIRECTION INPUT ;
    USE SIGNAL ;
    PORT
      LAYER M5 ;
        RECT 103.4880 164.0760 103.5120 164.1600 ;
    END
  END f_d[378]
  PIN f_d[379]
    DIRECTION INPUT ;
    USE SIGNAL ;
    PORT
      LAYER M5 ;
        RECT 103.7280 164.0760 103.7520 164.1600 ;
    END
  END f_d[379]
  PIN f_d[380]
    DIRECTION INPUT ;
    USE SIGNAL ;
    PORT
      LAYER M5 ;
        RECT 103.9680 164.0760 103.9920 164.1600 ;
    END
  END f_d[380]
  PIN f_d[381]
    DIRECTION INPUT ;
    USE SIGNAL ;
    PORT
      LAYER M5 ;
        RECT 104.2080 164.0760 104.2320 164.1600 ;
    END
  END f_d[381]
  PIN f_d[382]
    DIRECTION INPUT ;
    USE SIGNAL ;
    PORT
      LAYER M5 ;
        RECT 104.4480 164.0760 104.4720 164.1600 ;
    END
  END f_d[382]
  PIN f_d[383]
    DIRECTION INPUT ;
    USE SIGNAL ;
    PORT
      LAYER M5 ;
        RECT 104.6880 164.0760 104.7120 164.1600 ;
    END
  END f_d[383]
  PIN f_d[384]
    DIRECTION INPUT ;
    USE SIGNAL ;
    PORT
      LAYER M5 ;
        RECT 104.9280 164.0760 104.9520 164.1600 ;
    END
  END f_d[384]
  PIN f_d[385]
    DIRECTION INPUT ;
    USE SIGNAL ;
    PORT
      LAYER M5 ;
        RECT 105.1680 164.0760 105.1920 164.1600 ;
    END
  END f_d[385]
  PIN f_d[386]
    DIRECTION INPUT ;
    USE SIGNAL ;
    PORT
      LAYER M5 ;
        RECT 105.4080 164.0760 105.4320 164.1600 ;
    END
  END f_d[386]
  PIN f_d[387]
    DIRECTION INPUT ;
    USE SIGNAL ;
    PORT
      LAYER M5 ;
        RECT 105.6480 164.0760 105.6720 164.1600 ;
    END
  END f_d[387]
  PIN f_d[388]
    DIRECTION INPUT ;
    USE SIGNAL ;
    PORT
      LAYER M5 ;
        RECT 105.8880 164.0760 105.9120 164.1600 ;
    END
  END f_d[388]
  PIN f_d[389]
    DIRECTION INPUT ;
    USE SIGNAL ;
    PORT
      LAYER M5 ;
        RECT 106.1280 164.0760 106.1520 164.1600 ;
    END
  END f_d[389]
  PIN f_d[390]
    DIRECTION INPUT ;
    USE SIGNAL ;
    PORT
      LAYER M5 ;
        RECT 106.3680 164.0760 106.3920 164.1600 ;
    END
  END f_d[390]
  PIN f_d[391]
    DIRECTION INPUT ;
    USE SIGNAL ;
    PORT
      LAYER M5 ;
        RECT 106.6080 164.0760 106.6320 164.1600 ;
    END
  END f_d[391]
  PIN f_d[392]
    DIRECTION INPUT ;
    USE SIGNAL ;
    PORT
      LAYER M5 ;
        RECT 106.8480 164.0760 106.8720 164.1600 ;
    END
  END f_d[392]
  PIN f_d[393]
    DIRECTION INPUT ;
    USE SIGNAL ;
    PORT
      LAYER M5 ;
        RECT 107.0880 164.0760 107.1120 164.1600 ;
    END
  END f_d[393]
  PIN f_d[394]
    DIRECTION INPUT ;
    USE SIGNAL ;
    PORT
      LAYER M5 ;
        RECT 107.3280 164.0760 107.3520 164.1600 ;
    END
  END f_d[394]
  PIN f_d[395]
    DIRECTION INPUT ;
    USE SIGNAL ;
    PORT
      LAYER M5 ;
        RECT 107.5680 164.0760 107.5920 164.1600 ;
    END
  END f_d[395]
  PIN f_d[396]
    DIRECTION INPUT ;
    USE SIGNAL ;
    PORT
      LAYER M5 ;
        RECT 107.8080 164.0760 107.8320 164.1600 ;
    END
  END f_d[396]
  PIN f_d[397]
    DIRECTION INPUT ;
    USE SIGNAL ;
    PORT
      LAYER M5 ;
        RECT 108.0480 164.0760 108.0720 164.1600 ;
    END
  END f_d[397]
  PIN f_d[398]
    DIRECTION INPUT ;
    USE SIGNAL ;
    PORT
      LAYER M5 ;
        RECT 108.2880 164.0760 108.3120 164.1600 ;
    END
  END f_d[398]
  PIN f_d[399]
    DIRECTION INPUT ;
    USE SIGNAL ;
    PORT
      LAYER M5 ;
        RECT 108.5280 164.0760 108.5520 164.1600 ;
    END
  END f_d[399]
  PIN f_d[400]
    DIRECTION INPUT ;
    USE SIGNAL ;
    PORT
      LAYER M5 ;
        RECT 108.7680 164.0760 108.7920 164.1600 ;
    END
  END f_d[400]
  PIN f_d[401]
    DIRECTION INPUT ;
    USE SIGNAL ;
    PORT
      LAYER M5 ;
        RECT 109.0080 164.0760 109.0320 164.1600 ;
    END
  END f_d[401]
  PIN f_d[402]
    DIRECTION INPUT ;
    USE SIGNAL ;
    PORT
      LAYER M5 ;
        RECT 109.2480 164.0760 109.2720 164.1600 ;
    END
  END f_d[402]
  PIN f_d[403]
    DIRECTION INPUT ;
    USE SIGNAL ;
    PORT
      LAYER M5 ;
        RECT 109.4880 164.0760 109.5120 164.1600 ;
    END
  END f_d[403]
  PIN f_d[404]
    DIRECTION INPUT ;
    USE SIGNAL ;
    PORT
      LAYER M5 ;
        RECT 109.7280 164.0760 109.7520 164.1600 ;
    END
  END f_d[404]
  PIN f_d[405]
    DIRECTION INPUT ;
    USE SIGNAL ;
    PORT
      LAYER M5 ;
        RECT 109.9680 164.0760 109.9920 164.1600 ;
    END
  END f_d[405]
  PIN f_d[406]
    DIRECTION INPUT ;
    USE SIGNAL ;
    PORT
      LAYER M5 ;
        RECT 110.2080 164.0760 110.2320 164.1600 ;
    END
  END f_d[406]
  PIN f_d[407]
    DIRECTION INPUT ;
    USE SIGNAL ;
    PORT
      LAYER M5 ;
        RECT 110.4480 164.0760 110.4720 164.1600 ;
    END
  END f_d[407]
  PIN f_d[408]
    DIRECTION INPUT ;
    USE SIGNAL ;
    PORT
      LAYER M5 ;
        RECT 110.6880 164.0760 110.7120 164.1600 ;
    END
  END f_d[408]
  PIN f_d[409]
    DIRECTION INPUT ;
    USE SIGNAL ;
    PORT
      LAYER M5 ;
        RECT 110.9280 164.0760 110.9520 164.1600 ;
    END
  END f_d[409]
  PIN f_d[410]
    DIRECTION INPUT ;
    USE SIGNAL ;
    PORT
      LAYER M5 ;
        RECT 111.1680 164.0760 111.1920 164.1600 ;
    END
  END f_d[410]
  PIN f_d[411]
    DIRECTION INPUT ;
    USE SIGNAL ;
    PORT
      LAYER M5 ;
        RECT 111.4080 164.0760 111.4320 164.1600 ;
    END
  END f_d[411]
  PIN f_d[412]
    DIRECTION INPUT ;
    USE SIGNAL ;
    PORT
      LAYER M5 ;
        RECT 111.6480 164.0760 111.6720 164.1600 ;
    END
  END f_d[412]
  PIN f_d[413]
    DIRECTION INPUT ;
    USE SIGNAL ;
    PORT
      LAYER M5 ;
        RECT 111.8880 164.0760 111.9120 164.1600 ;
    END
  END f_d[413]
  PIN f_d[414]
    DIRECTION INPUT ;
    USE SIGNAL ;
    PORT
      LAYER M5 ;
        RECT 112.1280 164.0760 112.1520 164.1600 ;
    END
  END f_d[414]
  PIN f_d[415]
    DIRECTION INPUT ;
    USE SIGNAL ;
    PORT
      LAYER M5 ;
        RECT 112.3680 164.0760 112.3920 164.1600 ;
    END
  END f_d[415]
  PIN f_d[416]
    DIRECTION INPUT ;
    USE SIGNAL ;
    PORT
      LAYER M5 ;
        RECT 112.6080 164.0760 112.6320 164.1600 ;
    END
  END f_d[416]
  PIN f_d[417]
    DIRECTION INPUT ;
    USE SIGNAL ;
    PORT
      LAYER M5 ;
        RECT 112.8480 164.0760 112.8720 164.1600 ;
    END
  END f_d[417]
  PIN f_d[418]
    DIRECTION INPUT ;
    USE SIGNAL ;
    PORT
      LAYER M5 ;
        RECT 113.0880 164.0760 113.1120 164.1600 ;
    END
  END f_d[418]
  PIN f_d[419]
    DIRECTION INPUT ;
    USE SIGNAL ;
    PORT
      LAYER M5 ;
        RECT 113.3280 164.0760 113.3520 164.1600 ;
    END
  END f_d[419]
  PIN f_d[420]
    DIRECTION INPUT ;
    USE SIGNAL ;
    PORT
      LAYER M5 ;
        RECT 113.5680 164.0760 113.5920 164.1600 ;
    END
  END f_d[420]
  PIN f_d[421]
    DIRECTION INPUT ;
    USE SIGNAL ;
    PORT
      LAYER M5 ;
        RECT 113.8080 164.0760 113.8320 164.1600 ;
    END
  END f_d[421]
  PIN f_d[422]
    DIRECTION INPUT ;
    USE SIGNAL ;
    PORT
      LAYER M5 ;
        RECT 114.0480 164.0760 114.0720 164.1600 ;
    END
  END f_d[422]
  PIN f_d[423]
    DIRECTION INPUT ;
    USE SIGNAL ;
    PORT
      LAYER M5 ;
        RECT 114.2880 164.0760 114.3120 164.1600 ;
    END
  END f_d[423]
  PIN f_d[424]
    DIRECTION INPUT ;
    USE SIGNAL ;
    PORT
      LAYER M5 ;
        RECT 114.4800 164.0760 114.5040 164.1600 ;
    END
  END f_d[424]
  PIN f_d[425]
    DIRECTION INPUT ;
    USE SIGNAL ;
    PORT
      LAYER M5 ;
        RECT 114.7200 164.0760 114.7440 164.1600 ;
    END
  END f_d[425]
  PIN f_d[426]
    DIRECTION INPUT ;
    USE SIGNAL ;
    PORT
      LAYER M5 ;
        RECT 114.9600 164.0760 114.9840 164.1600 ;
    END
  END f_d[426]
  PIN f_d[427]
    DIRECTION INPUT ;
    USE SIGNAL ;
    PORT
      LAYER M5 ;
        RECT 115.2000 164.0760 115.2240 164.1600 ;
    END
  END f_d[427]
  PIN f_d[428]
    DIRECTION INPUT ;
    USE SIGNAL ;
    PORT
      LAYER M5 ;
        RECT 115.4400 164.0760 115.4640 164.1600 ;
    END
  END f_d[428]
  PIN f_d[429]
    DIRECTION INPUT ;
    USE SIGNAL ;
    PORT
      LAYER M5 ;
        RECT 115.6800 164.0760 115.7040 164.1600 ;
    END
  END f_d[429]
  PIN f_d[430]
    DIRECTION INPUT ;
    USE SIGNAL ;
    PORT
      LAYER M5 ;
        RECT 115.9200 164.0760 115.9440 164.1600 ;
    END
  END f_d[430]
  PIN f_d[431]
    DIRECTION INPUT ;
    USE SIGNAL ;
    PORT
      LAYER M5 ;
        RECT 116.1600 164.0760 116.1840 164.1600 ;
    END
  END f_d[431]
  PIN f_d[432]
    DIRECTION INPUT ;
    USE SIGNAL ;
    PORT
      LAYER M5 ;
        RECT 116.4000 164.0760 116.4240 164.1600 ;
    END
  END f_d[432]
  PIN f_d[433]
    DIRECTION INPUT ;
    USE SIGNAL ;
    PORT
      LAYER M5 ;
        RECT 116.6400 164.0760 116.6640 164.1600 ;
    END
  END f_d[433]
  PIN f_d[434]
    DIRECTION INPUT ;
    USE SIGNAL ;
    PORT
      LAYER M5 ;
        RECT 116.8800 164.0760 116.9040 164.1600 ;
    END
  END f_d[434]
  PIN f_d[435]
    DIRECTION INPUT ;
    USE SIGNAL ;
    PORT
      LAYER M5 ;
        RECT 117.1200 164.0760 117.1440 164.1600 ;
    END
  END f_d[435]
  PIN f_d[436]
    DIRECTION INPUT ;
    USE SIGNAL ;
    PORT
      LAYER M5 ;
        RECT 117.3600 164.0760 117.3840 164.1600 ;
    END
  END f_d[436]
  PIN f_d[437]
    DIRECTION INPUT ;
    USE SIGNAL ;
    PORT
      LAYER M5 ;
        RECT 117.6000 164.0760 117.6240 164.1600 ;
    END
  END f_d[437]
  PIN f_d[438]
    DIRECTION INPUT ;
    USE SIGNAL ;
    PORT
      LAYER M5 ;
        RECT 117.8400 164.0760 117.8640 164.1600 ;
    END
  END f_d[438]
  PIN f_d[439]
    DIRECTION INPUT ;
    USE SIGNAL ;
    PORT
      LAYER M5 ;
        RECT 118.0800 164.0760 118.1040 164.1600 ;
    END
  END f_d[439]
  PIN f_d[440]
    DIRECTION INPUT ;
    USE SIGNAL ;
    PORT
      LAYER M5 ;
        RECT 118.3200 164.0760 118.3440 164.1600 ;
    END
  END f_d[440]
  PIN f_d[441]
    DIRECTION INPUT ;
    USE SIGNAL ;
    PORT
      LAYER M5 ;
        RECT 118.5600 164.0760 118.5840 164.1600 ;
    END
  END f_d[441]
  PIN f_d[442]
    DIRECTION INPUT ;
    USE SIGNAL ;
    PORT
      LAYER M5 ;
        RECT 118.8000 164.0760 118.8240 164.1600 ;
    END
  END f_d[442]
  PIN f_d[443]
    DIRECTION INPUT ;
    USE SIGNAL ;
    PORT
      LAYER M5 ;
        RECT 119.0400 164.0760 119.0640 164.1600 ;
    END
  END f_d[443]
  PIN f_d[444]
    DIRECTION INPUT ;
    USE SIGNAL ;
    PORT
      LAYER M5 ;
        RECT 119.2800 164.0760 119.3040 164.1600 ;
    END
  END f_d[444]
  PIN f_d[445]
    DIRECTION INPUT ;
    USE SIGNAL ;
    PORT
      LAYER M5 ;
        RECT 119.5200 164.0760 119.5440 164.1600 ;
    END
  END f_d[445]
  PIN f_d[446]
    DIRECTION INPUT ;
    USE SIGNAL ;
    PORT
      LAYER M5 ;
        RECT 119.7600 164.0760 119.7840 164.1600 ;
    END
  END f_d[446]
  PIN f_d[447]
    DIRECTION INPUT ;
    USE SIGNAL ;
    PORT
      LAYER M5 ;
        RECT 120.0000 164.0760 120.0240 164.1600 ;
    END
  END f_d[447]
  PIN f_d[448]
    DIRECTION INPUT ;
    USE SIGNAL ;
    PORT
      LAYER M5 ;
        RECT 120.2400 164.0760 120.2640 164.1600 ;
    END
  END f_d[448]
  PIN f_d[449]
    DIRECTION INPUT ;
    USE SIGNAL ;
    PORT
      LAYER M5 ;
        RECT 120.4800 164.0760 120.5040 164.1600 ;
    END
  END f_d[449]
  PIN f_d[450]
    DIRECTION INPUT ;
    USE SIGNAL ;
    PORT
      LAYER M5 ;
        RECT 120.7200 164.0760 120.7440 164.1600 ;
    END
  END f_d[450]
  PIN f_d[451]
    DIRECTION INPUT ;
    USE SIGNAL ;
    PORT
      LAYER M5 ;
        RECT 120.9600 164.0760 120.9840 164.1600 ;
    END
  END f_d[451]
  PIN f_d[452]
    DIRECTION INPUT ;
    USE SIGNAL ;
    PORT
      LAYER M5 ;
        RECT 121.2000 164.0760 121.2240 164.1600 ;
    END
  END f_d[452]
  PIN f_d[453]
    DIRECTION INPUT ;
    USE SIGNAL ;
    PORT
      LAYER M5 ;
        RECT 121.4400 164.0760 121.4640 164.1600 ;
    END
  END f_d[453]
  PIN f_d[454]
    DIRECTION INPUT ;
    USE SIGNAL ;
    PORT
      LAYER M5 ;
        RECT 121.6800 164.0760 121.7040 164.1600 ;
    END
  END f_d[454]
  PIN f_d[455]
    DIRECTION INPUT ;
    USE SIGNAL ;
    PORT
      LAYER M5 ;
        RECT 121.9200 164.0760 121.9440 164.1600 ;
    END
  END f_d[455]
  PIN f_d[456]
    DIRECTION INPUT ;
    USE SIGNAL ;
    PORT
      LAYER M5 ;
        RECT 122.1600 164.0760 122.1840 164.1600 ;
    END
  END f_d[456]
  PIN f_d[457]
    DIRECTION INPUT ;
    USE SIGNAL ;
    PORT
      LAYER M5 ;
        RECT 122.4000 164.0760 122.4240 164.1600 ;
    END
  END f_d[457]
  PIN f_d[458]
    DIRECTION INPUT ;
    USE SIGNAL ;
    PORT
      LAYER M5 ;
        RECT 122.6400 164.0760 122.6640 164.1600 ;
    END
  END f_d[458]
  PIN f_d[459]
    DIRECTION INPUT ;
    USE SIGNAL ;
    PORT
      LAYER M5 ;
        RECT 122.8800 164.0760 122.9040 164.1600 ;
    END
  END f_d[459]
  PIN f_d[460]
    DIRECTION INPUT ;
    USE SIGNAL ;
    PORT
      LAYER M5 ;
        RECT 123.1200 164.0760 123.1440 164.1600 ;
    END
  END f_d[460]
  PIN f_d[461]
    DIRECTION INPUT ;
    USE SIGNAL ;
    PORT
      LAYER M5 ;
        RECT 123.3600 164.0760 123.3840 164.1600 ;
    END
  END f_d[461]
  PIN f_d[462]
    DIRECTION INPUT ;
    USE SIGNAL ;
    PORT
      LAYER M5 ;
        RECT 123.6000 164.0760 123.6240 164.1600 ;
    END
  END f_d[462]
  PIN f_d[463]
    DIRECTION INPUT ;
    USE SIGNAL ;
    PORT
      LAYER M5 ;
        RECT 123.8400 164.0760 123.8640 164.1600 ;
    END
  END f_d[463]
  PIN f_d[464]
    DIRECTION INPUT ;
    USE SIGNAL ;
    PORT
      LAYER M5 ;
        RECT 124.0800 164.0760 124.1040 164.1600 ;
    END
  END f_d[464]
  PIN f_d[465]
    DIRECTION INPUT ;
    USE SIGNAL ;
    PORT
      LAYER M5 ;
        RECT 124.3200 164.0760 124.3440 164.1600 ;
    END
  END f_d[465]
  PIN f_d[466]
    DIRECTION INPUT ;
    USE SIGNAL ;
    PORT
      LAYER M5 ;
        RECT 124.5600 164.0760 124.5840 164.1600 ;
    END
  END f_d[466]
  PIN f_d[467]
    DIRECTION INPUT ;
    USE SIGNAL ;
    PORT
      LAYER M5 ;
        RECT 124.8000 164.0760 124.8240 164.1600 ;
    END
  END f_d[467]
  PIN f_d[468]
    DIRECTION INPUT ;
    USE SIGNAL ;
    PORT
      LAYER M5 ;
        RECT 125.0400 164.0760 125.0640 164.1600 ;
    END
  END f_d[468]
  PIN f_d[469]
    DIRECTION INPUT ;
    USE SIGNAL ;
    PORT
      LAYER M5 ;
        RECT 125.2800 164.0760 125.3040 164.1600 ;
    END
  END f_d[469]
  PIN f_d[470]
    DIRECTION INPUT ;
    USE SIGNAL ;
    PORT
      LAYER M5 ;
        RECT 125.5200 164.0760 125.5440 164.1600 ;
    END
  END f_d[470]
  PIN f_d[471]
    DIRECTION INPUT ;
    USE SIGNAL ;
    PORT
      LAYER M5 ;
        RECT 125.7600 164.0760 125.7840 164.1600 ;
    END
  END f_d[471]
  PIN f_d[472]
    DIRECTION INPUT ;
    USE SIGNAL ;
    PORT
      LAYER M5 ;
        RECT 126.0000 164.0760 126.0240 164.1600 ;
    END
  END f_d[472]
  PIN f_d[473]
    DIRECTION INPUT ;
    USE SIGNAL ;
    PORT
      LAYER M5 ;
        RECT 126.2400 164.0760 126.2640 164.1600 ;
    END
  END f_d[473]
  PIN f_d[474]
    DIRECTION INPUT ;
    USE SIGNAL ;
    PORT
      LAYER M5 ;
        RECT 126.4800 164.0760 126.5040 164.1600 ;
    END
  END f_d[474]
  PIN f_d[475]
    DIRECTION INPUT ;
    USE SIGNAL ;
    PORT
      LAYER M5 ;
        RECT 126.7200 164.0760 126.7440 164.1600 ;
    END
  END f_d[475]
  PIN f_d[476]
    DIRECTION INPUT ;
    USE SIGNAL ;
    PORT
      LAYER M5 ;
        RECT 126.9600 164.0760 126.9840 164.1600 ;
    END
  END f_d[476]
  PIN f_d[477]
    DIRECTION INPUT ;
    USE SIGNAL ;
    PORT
      LAYER M5 ;
        RECT 127.2000 164.0760 127.2240 164.1600 ;
    END
  END f_d[477]
  PIN f_d[478]
    DIRECTION INPUT ;
    USE SIGNAL ;
    PORT
      LAYER M5 ;
        RECT 127.4400 164.0760 127.4640 164.1600 ;
    END
  END f_d[478]
  PIN f_d[479]
    DIRECTION INPUT ;
    USE SIGNAL ;
    PORT
      LAYER M5 ;
        RECT 127.6800 164.0760 127.7040 164.1600 ;
    END
  END f_d[479]
  PIN r_v
    DIRECTION OUTPUT ;
    USE SIGNAL ;
    PORT
      LAYER M5 ;
        RECT 127.9200 164.0760 127.9440 164.1600 ;
    END
  END r_v
  PIN r_hh[0]
    DIRECTION OUTPUT ;
    USE SIGNAL ;
    PORT
      LAYER M5 ;
        RECT 128.1600 164.0760 128.1840 164.1600 ;
    END
  END r_hh[0]
  PIN r_hh[1]
    DIRECTION OUTPUT ;
    USE SIGNAL ;
    PORT
      LAYER M5 ;
        RECT 128.4000 164.0760 128.4240 164.1600 ;
    END
  END r_hh[1]
  PIN r_hh[2]
    DIRECTION OUTPUT ;
    USE SIGNAL ;
    PORT
      LAYER M5 ;
        RECT 128.6400 164.0760 128.6640 164.1600 ;
    END
  END r_hh[2]
  PIN r_hh[3]
    DIRECTION OUTPUT ;
    USE SIGNAL ;
    PORT
      LAYER M5 ;
        RECT 128.8800 164.0760 128.9040 164.1600 ;
    END
  END r_hh[3]
  PIN r_hh[4]
    DIRECTION OUTPUT ;
    USE SIGNAL ;
    PORT
      LAYER M5 ;
        RECT 129.1200 164.0760 129.1440 164.1600 ;
    END
  END r_hh[4]
  PIN r_hh[5]
    DIRECTION OUTPUT ;
    USE SIGNAL ;
    PORT
      LAYER M5 ;
        RECT 129.3600 164.0760 129.3840 164.1600 ;
    END
  END r_hh[5]
  PIN r_hh[6]
    DIRECTION OUTPUT ;
    USE SIGNAL ;
    PORT
      LAYER M5 ;
        RECT 129.6000 164.0760 129.6240 164.1600 ;
    END
  END r_hh[6]
  PIN r_hh[7]
    DIRECTION OUTPUT ;
    USE SIGNAL ;
    PORT
      LAYER M5 ;
        RECT 129.8400 164.0760 129.8640 164.1600 ;
    END
  END r_hh[7]
  PIN r_hh[8]
    DIRECTION OUTPUT ;
    USE SIGNAL ;
    PORT
      LAYER M5 ;
        RECT 130.0800 164.0760 130.1040 164.1600 ;
    END
  END r_hh[8]
  PIN r_hh[9]
    DIRECTION OUTPUT ;
    USE SIGNAL ;
    PORT
      LAYER M5 ;
        RECT 130.3200 164.0760 130.3440 164.1600 ;
    END
  END r_hh[9]
  PIN r_hh[10]
    DIRECTION OUTPUT ;
    USE SIGNAL ;
    PORT
      LAYER M5 ;
        RECT 130.5600 164.0760 130.5840 164.1600 ;
    END
  END r_hh[10]
  PIN r_hh[11]
    DIRECTION OUTPUT ;
    USE SIGNAL ;
    PORT
      LAYER M5 ;
        RECT 130.8000 164.0760 130.8240 164.1600 ;
    END
  END r_hh[11]
  PIN r_hh[12]
    DIRECTION OUTPUT ;
    USE SIGNAL ;
    PORT
      LAYER M5 ;
        RECT 131.0400 164.0760 131.0640 164.1600 ;
    END
  END r_hh[12]
  PIN r_hh[13]
    DIRECTION OUTPUT ;
    USE SIGNAL ;
    PORT
      LAYER M5 ;
        RECT 131.2800 164.0760 131.3040 164.1600 ;
    END
  END r_hh[13]
  PIN r_hh[14]
    DIRECTION OUTPUT ;
    USE SIGNAL ;
    PORT
      LAYER M5 ;
        RECT 131.5200 164.0760 131.5440 164.1600 ;
    END
  END r_hh[14]
  PIN r_hh[15]
    DIRECTION OUTPUT ;
    USE SIGNAL ;
    PORT
      LAYER M5 ;
        RECT 131.7600 164.0760 131.7840 164.1600 ;
    END
  END r_hh[15]
  PIN r_hh[16]
    DIRECTION OUTPUT ;
    USE SIGNAL ;
    PORT
      LAYER M5 ;
        RECT 132.0000 164.0760 132.0240 164.1600 ;
    END
  END r_hh[16]
  PIN r_hh[17]
    DIRECTION OUTPUT ;
    USE SIGNAL ;
    PORT
      LAYER M5 ;
        RECT 132.2400 164.0760 132.2640 164.1600 ;
    END
  END r_hh[17]
  PIN r_hh[18]
    DIRECTION OUTPUT ;
    USE SIGNAL ;
    PORT
      LAYER M5 ;
        RECT 132.4800 164.0760 132.5040 164.1600 ;
    END
  END r_hh[18]
  PIN r_hh[19]
    DIRECTION OUTPUT ;
    USE SIGNAL ;
    PORT
      LAYER M5 ;
        RECT 132.7200 164.0760 132.7440 164.1600 ;
    END
  END r_hh[19]
  PIN r_hh[20]
    DIRECTION OUTPUT ;
    USE SIGNAL ;
    PORT
      LAYER M5 ;
        RECT 132.9600 164.0760 132.9840 164.1600 ;
    END
  END r_hh[20]
  PIN r_hh[21]
    DIRECTION OUTPUT ;
    USE SIGNAL ;
    PORT
      LAYER M5 ;
        RECT 133.2000 164.0760 133.2240 164.1600 ;
    END
  END r_hh[21]
  PIN r_hh[22]
    DIRECTION OUTPUT ;
    USE SIGNAL ;
    PORT
      LAYER M5 ;
        RECT 133.4400 164.0760 133.4640 164.1600 ;
    END
  END r_hh[22]
  PIN r_hh[23]
    DIRECTION OUTPUT ;
    USE SIGNAL ;
    PORT
      LAYER M5 ;
        RECT 133.6800 164.0760 133.7040 164.1600 ;
    END
  END r_hh[23]
  PIN r_hh[24]
    DIRECTION OUTPUT ;
    USE SIGNAL ;
    PORT
      LAYER M5 ;
        RECT 133.9200 164.0760 133.9440 164.1600 ;
    END
  END r_hh[24]
  PIN r_hh[25]
    DIRECTION OUTPUT ;
    USE SIGNAL ;
    PORT
      LAYER M5 ;
        RECT 134.1600 164.0760 134.1840 164.1600 ;
    END
  END r_hh[25]
  PIN r_hh[26]
    DIRECTION OUTPUT ;
    USE SIGNAL ;
    PORT
      LAYER M5 ;
        RECT 134.4000 164.0760 134.4240 164.1600 ;
    END
  END r_hh[26]
  PIN r_hh[27]
    DIRECTION OUTPUT ;
    USE SIGNAL ;
    PORT
      LAYER M5 ;
        RECT 134.6400 164.0760 134.6640 164.1600 ;
    END
  END r_hh[27]
  PIN r_hh[28]
    DIRECTION OUTPUT ;
    USE SIGNAL ;
    PORT
      LAYER M5 ;
        RECT 134.8800 164.0760 134.9040 164.1600 ;
    END
  END r_hh[28]
  PIN r_hh[29]
    DIRECTION OUTPUT ;
    USE SIGNAL ;
    PORT
      LAYER M5 ;
        RECT 135.1200 164.0760 135.1440 164.1600 ;
    END
  END r_hh[29]
  PIN r_hh[30]
    DIRECTION OUTPUT ;
    USE SIGNAL ;
    PORT
      LAYER M5 ;
        RECT 135.3600 164.0760 135.3840 164.1600 ;
    END
  END r_hh[30]
  PIN r_hh[31]
    DIRECTION OUTPUT ;
    USE SIGNAL ;
    PORT
      LAYER M5 ;
        RECT 135.6000 164.0760 135.6240 164.1600 ;
    END
  END r_hh[31]
  PIN r_kk[0]
    DIRECTION OUTPUT ;
    USE SIGNAL ;
    PORT
      LAYER M5 ;
        RECT 135.8400 164.0760 135.8640 164.1600 ;
    END
  END r_kk[0]
  PIN r_kk[1]
    DIRECTION OUTPUT ;
    USE SIGNAL ;
    PORT
      LAYER M5 ;
        RECT 136.0800 164.0760 136.1040 164.1600 ;
    END
  END r_kk[1]
  PIN r_kk[2]
    DIRECTION OUTPUT ;
    USE SIGNAL ;
    PORT
      LAYER M5 ;
        RECT 136.3200 164.0760 136.3440 164.1600 ;
    END
  END r_kk[2]
  PIN r_kk[3]
    DIRECTION OUTPUT ;
    USE SIGNAL ;
    PORT
      LAYER M5 ;
        RECT 136.5600 164.0760 136.5840 164.1600 ;
    END
  END r_kk[3]
  PIN r_kk[4]
    DIRECTION OUTPUT ;
    USE SIGNAL ;
    PORT
      LAYER M5 ;
        RECT 136.8000 164.0760 136.8240 164.1600 ;
    END
  END r_kk[4]
  PIN r_kk[5]
    DIRECTION OUTPUT ;
    USE SIGNAL ;
    PORT
      LAYER M5 ;
        RECT 137.0400 164.0760 137.0640 164.1600 ;
    END
  END r_kk[5]
  PIN r_kk[6]
    DIRECTION OUTPUT ;
    USE SIGNAL ;
    PORT
      LAYER M5 ;
        RECT 137.2800 164.0760 137.3040 164.1600 ;
    END
  END r_kk[6]
  PIN r_kk[7]
    DIRECTION OUTPUT ;
    USE SIGNAL ;
    PORT
      LAYER M5 ;
        RECT 137.5200 164.0760 137.5440 164.1600 ;
    END
  END r_kk[7]
  PIN r_kk[8]
    DIRECTION OUTPUT ;
    USE SIGNAL ;
    PORT
      LAYER M5 ;
        RECT 137.7600 164.0760 137.7840 164.1600 ;
    END
  END r_kk[8]
  PIN r_kk[9]
    DIRECTION OUTPUT ;
    USE SIGNAL ;
    PORT
      LAYER M5 ;
        RECT 138.0000 164.0760 138.0240 164.1600 ;
    END
  END r_kk[9]
  PIN r_kk[10]
    DIRECTION OUTPUT ;
    USE SIGNAL ;
    PORT
      LAYER M5 ;
        RECT 138.2400 164.0760 138.2640 164.1600 ;
    END
  END r_kk[10]
  PIN r_kk[11]
    DIRECTION OUTPUT ;
    USE SIGNAL ;
    PORT
      LAYER M5 ;
        RECT 138.4800 164.0760 138.5040 164.1600 ;
    END
  END r_kk[11]
  PIN r_kk[12]
    DIRECTION OUTPUT ;
    USE SIGNAL ;
    PORT
      LAYER M5 ;
        RECT 138.7200 164.0760 138.7440 164.1600 ;
    END
  END r_kk[12]
  PIN r_kk[13]
    DIRECTION OUTPUT ;
    USE SIGNAL ;
    PORT
      LAYER M5 ;
        RECT 138.9120 164.0760 138.9360 164.1600 ;
    END
  END r_kk[13]
  PIN r_kk[14]
    DIRECTION OUTPUT ;
    USE SIGNAL ;
    PORT
      LAYER M5 ;
        RECT 139.1520 164.0760 139.1760 164.1600 ;
    END
  END r_kk[14]
  PIN r_kk[15]
    DIRECTION OUTPUT ;
    USE SIGNAL ;
    PORT
      LAYER M5 ;
        RECT 139.3920 164.0760 139.4160 164.1600 ;
    END
  END r_kk[15]
  PIN r_kk[16]
    DIRECTION OUTPUT ;
    USE SIGNAL ;
    PORT
      LAYER M5 ;
        RECT 139.6320 164.0760 139.6560 164.1600 ;
    END
  END r_kk[16]
  PIN r_kk[17]
    DIRECTION OUTPUT ;
    USE SIGNAL ;
    PORT
      LAYER M5 ;
        RECT 139.8720 164.0760 139.8960 164.1600 ;
    END
  END r_kk[17]
  PIN r_kk[18]
    DIRECTION OUTPUT ;
    USE SIGNAL ;
    PORT
      LAYER M5 ;
        RECT 140.1120 164.0760 140.1360 164.1600 ;
    END
  END r_kk[18]
  PIN r_kk[19]
    DIRECTION OUTPUT ;
    USE SIGNAL ;
    PORT
      LAYER M5 ;
        RECT 140.3520 164.0760 140.3760 164.1600 ;
    END
  END r_kk[19]
  PIN r_kk[20]
    DIRECTION OUTPUT ;
    USE SIGNAL ;
    PORT
      LAYER M5 ;
        RECT 140.5920 164.0760 140.6160 164.1600 ;
    END
  END r_kk[20]
  PIN r_kk[21]
    DIRECTION OUTPUT ;
    USE SIGNAL ;
    PORT
      LAYER M5 ;
        RECT 140.8320 164.0760 140.8560 164.1600 ;
    END
  END r_kk[21]
  PIN r_kk[22]
    DIRECTION OUTPUT ;
    USE SIGNAL ;
    PORT
      LAYER M5 ;
        RECT 141.0720 164.0760 141.0960 164.1600 ;
    END
  END r_kk[22]
  PIN r_kk[23]
    DIRECTION OUTPUT ;
    USE SIGNAL ;
    PORT
      LAYER M5 ;
        RECT 141.3120 164.0760 141.3360 164.1600 ;
    END
  END r_kk[23]
  PIN r_kk[24]
    DIRECTION OUTPUT ;
    USE SIGNAL ;
    PORT
      LAYER M5 ;
        RECT 141.5520 164.0760 141.5760 164.1600 ;
    END
  END r_kk[24]
  PIN r_kk[25]
    DIRECTION OUTPUT ;
    USE SIGNAL ;
    PORT
      LAYER M5 ;
        RECT 141.7920 164.0760 141.8160 164.1600 ;
    END
  END r_kk[25]
  PIN r_kk[26]
    DIRECTION OUTPUT ;
    USE SIGNAL ;
    PORT
      LAYER M5 ;
        RECT 142.0320 164.0760 142.0560 164.1600 ;
    END
  END r_kk[26]
  PIN r_kk[27]
    DIRECTION OUTPUT ;
    USE SIGNAL ;
    PORT
      LAYER M5 ;
        RECT 142.2720 164.0760 142.2960 164.1600 ;
    END
  END r_kk[27]
  PIN r_kk[28]
    DIRECTION OUTPUT ;
    USE SIGNAL ;
    PORT
      LAYER M5 ;
        RECT 142.5120 164.0760 142.5360 164.1600 ;
    END
  END r_kk[28]
  PIN r_kk[29]
    DIRECTION OUTPUT ;
    USE SIGNAL ;
    PORT
      LAYER M5 ;
        RECT 142.7520 164.0760 142.7760 164.1600 ;
    END
  END r_kk[29]
  PIN r_kk[30]
    DIRECTION OUTPUT ;
    USE SIGNAL ;
    PORT
      LAYER M5 ;
        RECT 142.9920 164.0760 143.0160 164.1600 ;
    END
  END r_kk[30]
  PIN r_kk[31]
    DIRECTION OUTPUT ;
    USE SIGNAL ;
    PORT
      LAYER M5 ;
        RECT 143.2320 164.0760 143.2560 164.1600 ;
    END
  END r_kk[31]
  PIN r_dd[0]
    DIRECTION OUTPUT ;
    USE SIGNAL ;
    PORT
      LAYER M5 ;
        RECT 143.4720 164.0760 143.4960 164.1600 ;
    END
  END r_dd[0]
  PIN r_dd[1]
    DIRECTION OUTPUT ;
    USE SIGNAL ;
    PORT
      LAYER M5 ;
        RECT 143.7120 164.0760 143.7360 164.1600 ;
    END
  END r_dd[1]
  PIN r_dd[2]
    DIRECTION OUTPUT ;
    USE SIGNAL ;
    PORT
      LAYER M5 ;
        RECT 143.9520 164.0760 143.9760 164.1600 ;
    END
  END r_dd[2]
  PIN r_dd[3]
    DIRECTION OUTPUT ;
    USE SIGNAL ;
    PORT
      LAYER M5 ;
        RECT 144.1920 164.0760 144.2160 164.1600 ;
    END
  END r_dd[3]
  PIN r_dd[4]
    DIRECTION OUTPUT ;
    USE SIGNAL ;
    PORT
      LAYER M5 ;
        RECT 144.4320 164.0760 144.4560 164.1600 ;
    END
  END r_dd[4]
  PIN r_dd[5]
    DIRECTION OUTPUT ;
    USE SIGNAL ;
    PORT
      LAYER M5 ;
        RECT 144.6720 164.0760 144.6960 164.1600 ;
    END
  END r_dd[5]
  PIN r_dd[6]
    DIRECTION OUTPUT ;
    USE SIGNAL ;
    PORT
      LAYER M5 ;
        RECT 144.9120 164.0760 144.9360 164.1600 ;
    END
  END r_dd[6]
  PIN r_dd[7]
    DIRECTION OUTPUT ;
    USE SIGNAL ;
    PORT
      LAYER M5 ;
        RECT 145.1520 164.0760 145.1760 164.1600 ;
    END
  END r_dd[7]
  PIN r_dd[8]
    DIRECTION OUTPUT ;
    USE SIGNAL ;
    PORT
      LAYER M5 ;
        RECT 145.3920 164.0760 145.4160 164.1600 ;
    END
  END r_dd[8]
  PIN r_dd[9]
    DIRECTION OUTPUT ;
    USE SIGNAL ;
    PORT
      LAYER M5 ;
        RECT 145.6320 164.0760 145.6560 164.1600 ;
    END
  END r_dd[9]
  PIN r_dd[10]
    DIRECTION OUTPUT ;
    USE SIGNAL ;
    PORT
      LAYER M5 ;
        RECT 145.8720 164.0760 145.8960 164.1600 ;
    END
  END r_dd[10]
  PIN r_dd[11]
    DIRECTION OUTPUT ;
    USE SIGNAL ;
    PORT
      LAYER M5 ;
        RECT 146.1120 164.0760 146.1360 164.1600 ;
    END
  END r_dd[11]
  PIN r_dd[12]
    DIRECTION OUTPUT ;
    USE SIGNAL ;
    PORT
      LAYER M5 ;
        RECT 146.3520 164.0760 146.3760 164.1600 ;
    END
  END r_dd[12]
  PIN r_dd[13]
    DIRECTION OUTPUT ;
    USE SIGNAL ;
    PORT
      LAYER M5 ;
        RECT 146.5920 164.0760 146.6160 164.1600 ;
    END
  END r_dd[13]
  PIN r_dd[14]
    DIRECTION OUTPUT ;
    USE SIGNAL ;
    PORT
      LAYER M5 ;
        RECT 146.8320 164.0760 146.8560 164.1600 ;
    END
  END r_dd[14]
  PIN r_dd[15]
    DIRECTION OUTPUT ;
    USE SIGNAL ;
    PORT
      LAYER M5 ;
        RECT 147.0720 164.0760 147.0960 164.1600 ;
    END
  END r_dd[15]
  PIN r_dd[16]
    DIRECTION OUTPUT ;
    USE SIGNAL ;
    PORT
      LAYER M5 ;
        RECT 147.3120 164.0760 147.3360 164.1600 ;
    END
  END r_dd[16]
  PIN r_dd[17]
    DIRECTION OUTPUT ;
    USE SIGNAL ;
    PORT
      LAYER M5 ;
        RECT 147.5520 164.0760 147.5760 164.1600 ;
    END
  END r_dd[17]
  PIN r_dd[18]
    DIRECTION OUTPUT ;
    USE SIGNAL ;
    PORT
      LAYER M5 ;
        RECT 147.7920 164.0760 147.8160 164.1600 ;
    END
  END r_dd[18]
  PIN r_dd[19]
    DIRECTION OUTPUT ;
    USE SIGNAL ;
    PORT
      LAYER M5 ;
        RECT 148.0320 164.0760 148.0560 164.1600 ;
    END
  END r_dd[19]
  PIN r_dd[20]
    DIRECTION OUTPUT ;
    USE SIGNAL ;
    PORT
      LAYER M5 ;
        RECT 148.2720 164.0760 148.2960 164.1600 ;
    END
  END r_dd[20]
  PIN r_dd[21]
    DIRECTION OUTPUT ;
    USE SIGNAL ;
    PORT
      LAYER M5 ;
        RECT 148.5120 164.0760 148.5360 164.1600 ;
    END
  END r_dd[21]
  PIN r_dd[22]
    DIRECTION OUTPUT ;
    USE SIGNAL ;
    PORT
      LAYER M5 ;
        RECT 148.7520 164.0760 148.7760 164.1600 ;
    END
  END r_dd[22]
  PIN r_dd[23]
    DIRECTION OUTPUT ;
    USE SIGNAL ;
    PORT
      LAYER M5 ;
        RECT 148.9920 164.0760 149.0160 164.1600 ;
    END
  END r_dd[23]
  PIN r_dd[24]
    DIRECTION OUTPUT ;
    USE SIGNAL ;
    PORT
      LAYER M5 ;
        RECT 149.2320 164.0760 149.2560 164.1600 ;
    END
  END r_dd[24]
  PIN r_dd[25]
    DIRECTION OUTPUT ;
    USE SIGNAL ;
    PORT
      LAYER M5 ;
        RECT 149.4720 164.0760 149.4960 164.1600 ;
    END
  END r_dd[25]
  PIN r_dd[26]
    DIRECTION OUTPUT ;
    USE SIGNAL ;
    PORT
      LAYER M5 ;
        RECT 149.7120 164.0760 149.7360 164.1600 ;
    END
  END r_dd[26]
  PIN r_dd[27]
    DIRECTION OUTPUT ;
    USE SIGNAL ;
    PORT
      LAYER M5 ;
        RECT 149.9520 164.0760 149.9760 164.1600 ;
    END
  END r_dd[27]
  PIN r_dd[28]
    DIRECTION OUTPUT ;
    USE SIGNAL ;
    PORT
      LAYER M5 ;
        RECT 150.1920 164.0760 150.2160 164.1600 ;
    END
  END r_dd[28]
  PIN r_dd[29]
    DIRECTION OUTPUT ;
    USE SIGNAL ;
    PORT
      LAYER M5 ;
        RECT 150.4320 164.0760 150.4560 164.1600 ;
    END
  END r_dd[29]
  PIN r_dd[30]
    DIRECTION OUTPUT ;
    USE SIGNAL ;
    PORT
      LAYER M5 ;
        RECT 150.6720 164.0760 150.6960 164.1600 ;
    END
  END r_dd[30]
  PIN r_dd[31]
    DIRECTION OUTPUT ;
    USE SIGNAL ;
    PORT
      LAYER M5 ;
        RECT 150.9120 164.0760 150.9360 164.1600 ;
    END
  END r_dd[31]
  PIN fault
    DIRECTION OUTPUT ;
    USE SIGNAL ;
    PORT
      LAYER M5 ;
        RECT 151.1520 164.0760 151.1760 164.1600 ;
    END
  END fault
END ot_s81dv_eng_finish
END LIBRARY
